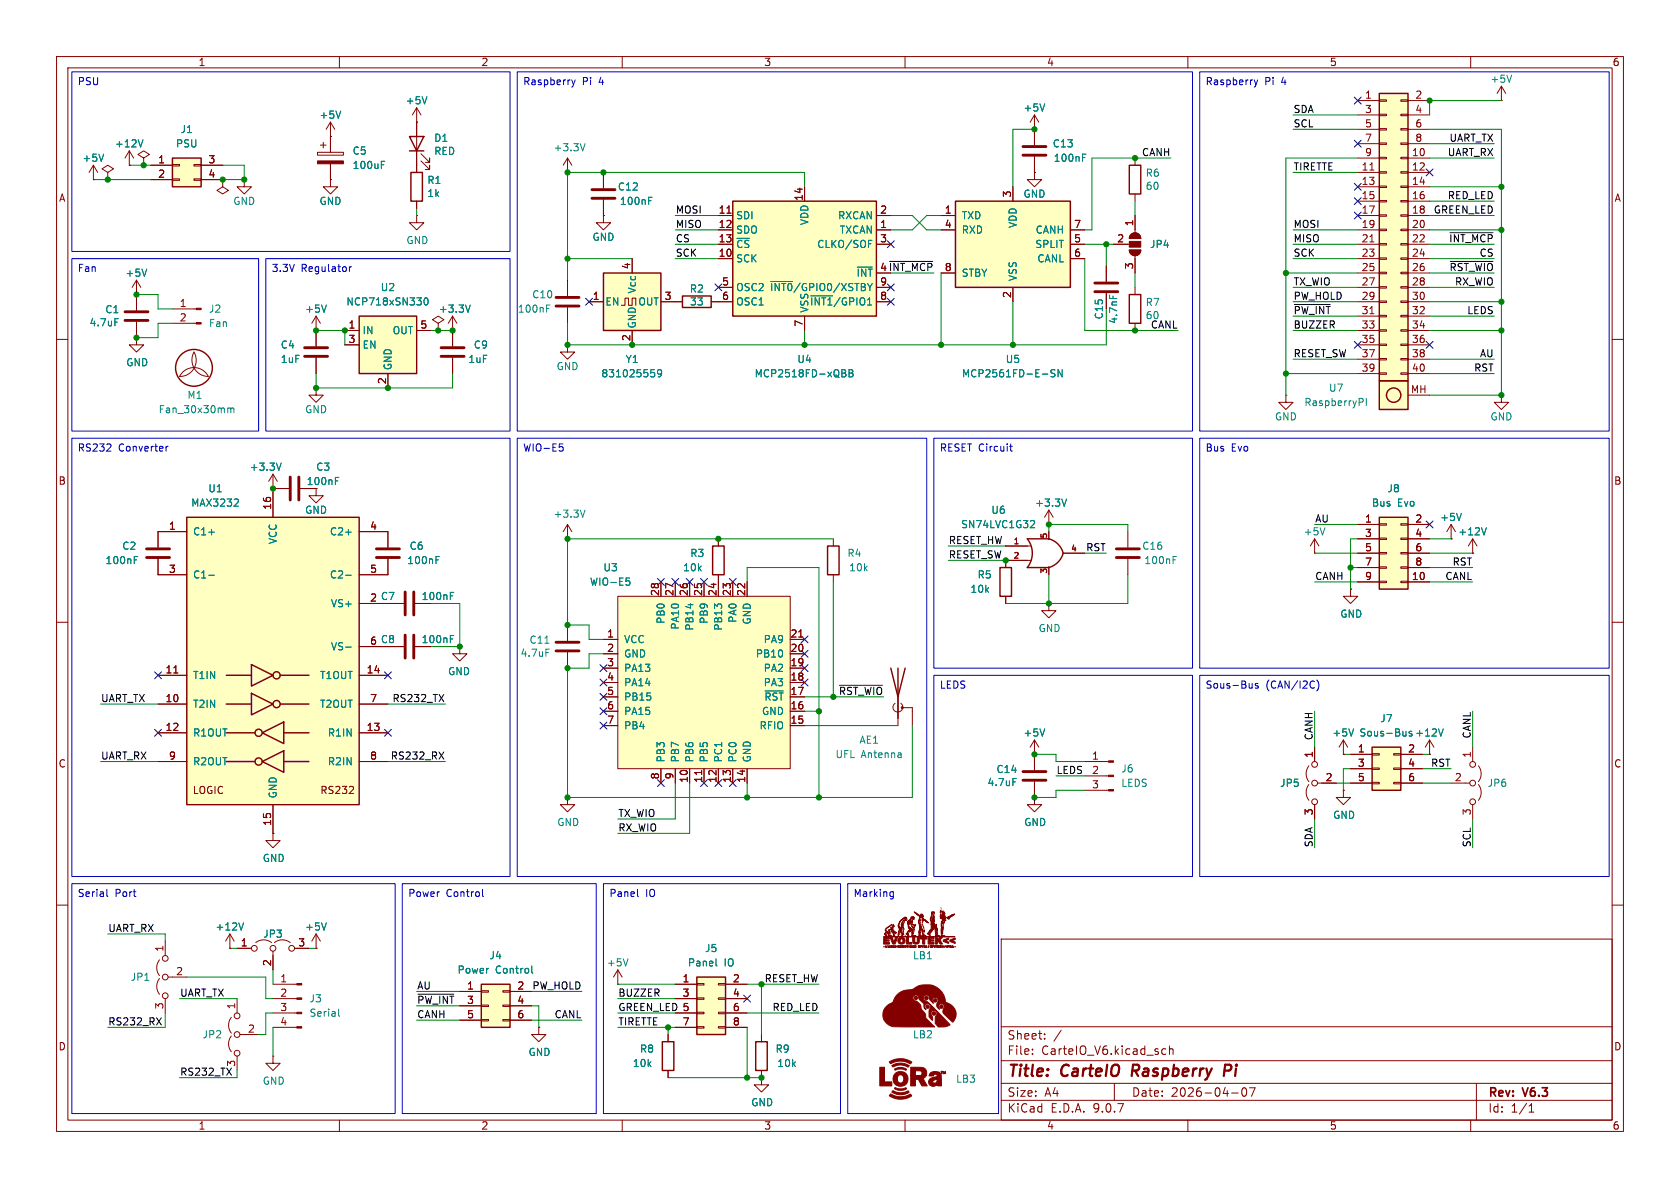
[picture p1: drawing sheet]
<svg xmlns="http://www.w3.org/2000/svg" width="297mm" height="210mm" viewBox="0 0 297 210" stroke-linecap="round" stroke-linejoin="round" font-family="sans-serif">
<defs><g id="words">
<g font-size="2.8" fill="#840000">
<text x="178" y="190.9">Title:</text>
<text x="187.7" y="190.9">CarteIO</text>
<text x="200.9" y="190.9">Raspberry</text>
<text x="218" y="190.9">Pi</text>
</g>
<g font-size="2.1" fill="#840000">
<text x="178" y="184">Sheet:</text>
<text x="178" y="186.7">File:</text>
<text x="184.1" y="186.7">CarteIO_V6.kicad_sch</text>
<text x="178" y="196.9">KiCad</text>
<text x="178" y="194.1">Size:</text>
<text x="184.7" y="194.1">A4</text>
<text x="185.7" y="196.9">E.D.A.</text>
<text x="193.3" y="196.9">9.0.7</text>
<text x="200" y="194.1">Date:</text>
<text x="207" y="194.1">2026-04-07</text>
<text x="263" y="194.3">Rev:</text>
<text x="263" y="196.9">Id:</text>
<text x="267.1" y="196.9">1/1</text>
<text x="269.4" y="194.3">V6.3</text>
</g>
<g font-size="1.8" fill="#840000">
<text x="35" y="11.9">1</text>
<text x="85" y="11.9">2</text>
<text x="135" y="11.9">3</text>
<text x="185" y="11.9">4</text>
<text x="235" y="11.9">5</text>
<text x="285" y="11.9">6</text>
<text x="241.2" y="17.5">1</text>
<text x="250.1" y="17.5">2</text>
<text x="241.2" y="20.1">3</text>
<text x="241.2" y="22.6">5</text>
<text x="250.1" y="20.1">4</text>
<text x="250.1" y="22.6">6</text>
<text x="27.9" y="29">1</text>
<text x="36.8" y="29">3</text>
<text x="241.2" y="25.1">7</text>
<text x="241.2" y="27.7">9</text>
<text x="249.5" y="27.7">10</text>
<text x="250.1" y="25.1">8</text>
<text x="10.3" y="35.9">A</text>
<text x="27.9" y="31.5">2</text>
<text x="36.8" y="31.5">4</text>
<text x="142" y="35.6" transform="rotate(-90 142 35.6)">14</text>
<text x="178.8" y="35" transform="rotate(-90 178.8 35)">3</text>
<text x="240.6" y="30.2">11</text>
<text x="240.6" y="32.8">13</text>
<text x="240.6" y="35.3">15</text>
<text x="249.5" y="30.2">12</text>
<text x="249.5" y="32.8">14</text>
<text x="249.5" y="35.3">16</text>
<text x="285.3" y="35.9">A</text>
<text x="127" y="37.8">11</text>
<text x="127" y="40.4">12</text>
<text x="155.5" y="37.8">2</text>
<text x="155.5" y="40.4">1</text>
<text x="166.9" y="37.8">1</text>
<text x="166.9" y="40.4">4</text>
<text x="189.8" y="40.4">7</text>
<text x="200.4" y="40.1" transform="rotate(-90 200.4 40.1)">1</text>
<text x="240.6" y="37.8">17</text>
<text x="240.6" y="40.4">19</text>
<text x="249.5" y="37.8">18</text>
<text x="249.5" y="40.4">20</text>
<text x="111.5" y="47.7" transform="rotate(-90 111.5 47.7)">4</text>
<text x="127" y="42.9">13</text>
<text x="127" y="45.5">10</text>
<text x="155.5" y="42.9">3</text>
<text x="189.8" y="42.9">5</text>
<text x="189.8" y="45.5">6</text>
<text x="197.4" y="42.9">2</text>
<text x="200.4" y="47.7" transform="rotate(-90 200.4 47.7)">3</text>
<text x="240.6" y="42.9">21</text>
<text x="240.6" y="45.5">23</text>
<text x="249.5" y="42.9">22</text>
<text x="249.5" y="45.5">24</text>
<text x="104.7" y="53.1">1</text>
<text x="117.4" y="53.1">3</text>
<text x="127.6" y="50.5">5</text>
<text x="127.6" y="53.1">6</text>
<text x="155.5" y="48">4 ~{INT_MCP}8</text>
<text x="155.5" y="50.5">9</text>
<text x="155.5" y="53.1">8</text>
<text x="155.5" y="48">4</text>
<text x="166.9" y="48">8</text>
<text x="178.8" y="52.8" transform="rotate(-90 178.8 52.8)">2</text>
<text x="240.6" y="48">25</text>
<text x="240.6" y="50.5">27</text>
<text x="240.6" y="53.1">29</text>
<text x="249.5" y="48">26</text>
<text x="249.5" y="50.5">28</text>
<text x="249.5" y="53.1">30</text>
<text x="31.7" y="54.4">1</text>
<text x="31.7" y="56.9">2</text>
<text x="61.5" y="58.2">1</text>
<text x="74.2" y="58.2">5</text>
<text x="142" y="57.9" transform="rotate(-90 142 57.9)">7</text>
<text x="240.6" y="55.6">31</text>
<text x="240.6" y="58.2">33</text>
<text x="249.5" y="55.6">32</text>
<text x="249.5" y="58.2">34</text>
<text x="61.5" y="60.7">3</text>
<text x="111.5" y="60.4" transform="rotate(-90 111.5 60.4)">2</text>
<text x="240.6" y="60.7">35</text>
<text x="240.6" y="63.2">37</text>
<text x="240.6" y="65.8">39</text>
<text x="249.5" y="60.7">36</text>
<text x="249.5" y="63.2">38</text>
<text x="249.5" y="65.8">40</text>
<text x="68.3" y="68" transform="rotate(-90 68.3 68)">2</text>
<text x="249.3" y="69.6">MH</text>
<text x="10.3" y="85.9">B</text>
<text x="54.1" y="86">100nF</text>
<text x="285.3" y="85.9">B</text>
<text x="29.8" y="93.7">1</text>
<text x="48" y="90.2" transform="rotate(-90 48 90.2)">16</text>
<text x="65.3" y="93.7">4</text>
<text x="241.2" y="92.5">1</text>
<text x="241.2" y="95">3</text>
<text x="250.1" y="92.5">2</text>
<text x="250.1" y="95">4</text>
<text x="29.8" y="101.3">3</text>
<text x="65.3" y="101.3">5</text>
<text x="241.2" y="97.5">5</text>
<text x="241.2" y="100.1">7</text>
<text x="250.1" y="97.5">6</text>
<text x="250.1" y="100.1">8</text>
<text x="65.3" y="106.4">2 C7</text>
<text x="116.6" y="105.5" transform="rotate(-90 116.6 105.5)">28</text>
<text x="119.1" y="105.5" transform="rotate(-90 119.1 105.5)">27</text>
<text x="121.7" y="105.5" transform="rotate(-90 121.7 105.5)">26</text>
<text x="124.2" y="105.5" transform="rotate(-90 124.2 105.5)">25</text>
<text x="126.7" y="105.5" transform="rotate(-90 126.7 105.5)">24</text>
<text x="129.3" y="105.5" transform="rotate(-90 129.3 105.5)">23</text>
<text x="131.8" y="105.5" transform="rotate(-90 131.8 105.5)">22</text>
<text x="241.2" y="102.6">9</text>
<text x="249.5" y="102.6">10</text>
<text x="107.2" y="112.8">1</text>
<text x="139.7" y="112.8">21</text>
<text x="29.2" y="119.1">11</text>
<text x="64.7" y="119.1">14</text>
<text x="65.3" y="114">6 C8</text>
<text x="107.2" y="115.3">2</text>
<text x="107.2" y="117.9">3</text>
<text x="139.7" y="115.3">20</text>
<text x="139.7" y="117.9">19</text>
<text x="29.2" y="124.2">10</text>
<text x="65.3" y="124.2">7</text>
<text x="107.2" y="120.4">4</text>
<text x="107.2" y="122.9">5</text>
<text x="107.2" y="125.5">6</text>
<text x="139.7" y="120.4">18</text>
<text x="139.7" y="122.9">17</text>
<text x="139.7" y="125.5">16</text>
<text x="29.2" y="129.3">12</text>
<text x="64.7" y="129.3">13</text>
<text x="107.2" y="128">7</text>
<text x="139.7" y="128">15</text>
<text x="10.3" y="135.9">C</text>
<text x="29.8" y="134.4">9</text>
<text x="65.3" y="134.4">8</text>
<text x="116.6" y="137.9" transform="rotate(-90 116.6 137.9)">8</text>
<text x="119.1" y="137.9" transform="rotate(-90 119.1 137.9)">9</text>
<text x="193" y="134.4">1</text>
<text x="193" y="136.9">2</text>
<text x="232.2" y="134.1" transform="rotate(-90 232.2 134.1)">1</text>
<text x="240" y="133.1">1</text>
<text x="240" y="135.6">3</text>
<text x="248.8" y="133.1">2</text>
<text x="248.8" y="135.6">4</text>
<text x="260.1" y="134.1" transform="rotate(-90 260.1 134.1)">1</text>
<text x="285.3" y="135.9">C</text>
<text x="34" y="140.6">LOGIC</text>
<text x="56.5" y="140.6">RS232</text>
<text x="121.7" y="138.5" transform="rotate(-90 121.7 138.5)">10</text>
<text x="124.2" y="138.5" transform="rotate(-90 124.2 138.5)">11</text>
<text x="126.7" y="138.5" transform="rotate(-90 126.7 138.5)">12</text>
<text x="129.3" y="138.5" transform="rotate(-90 129.3 138.5)">13</text>
<text x="131.8" y="138.5" transform="rotate(-90 131.8 138.5)">14</text>
<text x="193" y="139.4">3</text>
<text x="234.2" y="138.2">2</text>
<text x="240" y="138.2">5</text>
<text x="248.8" y="138.2">6</text>
<text x="257.1" y="138.2">2</text>
<text x="48" y="146.1" transform="rotate(-90 48 146.1)">15</text>
<text x="232.2" y="144.2" transform="rotate(-90 232.2 144.2)">3</text>
<text x="260.1" y="144.2" transform="rotate(-90 260.1 144.2)">3</text>
<text x="42.5" y="167.4">1</text>
<text x="52.6" y="167.4">3</text>
<text x="29" y="168.3" transform="rotate(-90 29 168.3)">1</text>
<text x="31" y="172.5">2</text>
<text x="48" y="170.9" transform="rotate(-90 48 170.9)">2</text>
<text x="49.5" y="173.7">1</text>
<text x="120.6" y="173.7">1</text>
<text x="129.5" y="173.7">2</text>
<text x="29" y="178.5" transform="rotate(-90 29 178.5)">3</text>
<text x="41.7" y="178.5" transform="rotate(-90 41.7 178.5)">1</text>
<text x="49.5" y="176.3">2</text>
<text x="49.5" y="178.8">3</text>
<text x="82.5" y="175">1</text>
<text x="82.5" y="177.5">3</text>
<text x="91.4" y="175">2</text>
<text x="91.4" y="177.5">4</text>
<text x="120.6" y="176.3">3</text>
<text x="120.6" y="178.8">5</text>
<text x="129.5" y="176.3">4</text>
<text x="129.5" y="178.8">6</text>
<text x="10.3" y="185.9">D</text>
<text x="43.7" y="182.6">2</text>
<text x="49.5" y="181.4">4</text>
<text x="82.5" y="180.1">5</text>
<text x="91.4" y="180.1">6</text>
<text x="120.6" y="181.4">7</text>
<text x="129.5" y="181.4">8</text>
<text x="285.3" y="185.9">D</text>
<text x="41.7" y="188.7" transform="rotate(-90 41.7 188.7)">3</text>
<text x="35" y="199.9">1</text>
<text x="85" y="199.9">2</text>
<text x="135" y="199.9">3</text>
<text x="185" y="199.9">4</text>
<text x="235" y="199.9">5</text>
<text x="285" y="199.9">6</text>
</g>
<g font-size="1.8" fill="#0000c2">
<text x="13.7" y="15.4">PSU</text>
<text x="92.4" y="15.4">Raspberry</text>
<text x="102.9" y="15.4">Pi</text>
<text x="106" y="15.4">4</text>
<text x="213" y="15.4">Raspberry</text>
<text x="223.6" y="15.4">Pi</text>
<text x="226.6" y="15.4">4</text>
<text x="13.7" y="48.4">Fan</text>
<text x="47.9" y="48.4">3.3V</text>
<text x="53.2" y="48.4">Regulator</text>
<text x="13.7" y="80.1">RS232</text>
<text x="20.9" y="80.1">Converter</text>
<text x="92.4" y="80.1">WIO-E5</text>
<text x="166.1" y="80.1">RESET Circuit</text>
<text x="213" y="80.1">Bus</text>
<text x="217.7" y="80.1">Evo</text>
<text x="166.1" y="122.1">LEDS</text>
<text x="213" y="122.1">Sous-Bus</text>
<text x="223.8" y="122.1">(CAN/I2C)</text>
<text x="13.7" y="158.9">Serial</text>
<text x="20.3" y="158.9">Port</text>
<text x="72.1" y="158.9">Power</text>
<text x="78.9" y="158.9">Control</text>
<text x="107.6" y="158.9">Panel</text>
<text x="114.1" y="158.9">IO</text>
<text x="150.8" y="158.9">Marking</text>
</g>
<g font-size="1.8" fill="#008484">
<text x="263.4" y="14.8">+5V</text>
<text x="31.8" y="23.7">J1</text>
<text x="56.4" y="21.2">+5V</text>
<text x="71.6" y="18.6">+5V</text>
<text x="180.8" y="19.9">+5V</text>
<text x="14.5" y="28.8">+5V</text>
<text x="20.2" y="26.3">+12V</text>
<text x="31" y="26.3">PSU</text>
<text x="62.2" y="27.5">C5</text>
<text x="76.7" y="25.3">D1</text>
<text x="76.7" y="27.6">RED</text>
<text x="97.8" y="26.9">+3.3V</text>
<text x="186" y="26.3">C13</text>
<text x="186.2" y="28.8">100nF</text>
<text x="62.2" y="30.1">100uF</text>
<text x="75.4" y="32.7">R1</text>
<text x="75.4" y="35">1k</text>
<text x="109.1" y="33.9">C12</text>
<text x="180.8" y="35.2">GND</text>
<text x="202.4" y="31.4">R6</text>
<text x="202.4" y="33.8">60</text>
<text x="41.1" y="36.4">GND</text>
<text x="56.4" y="36.4">GND</text>
<text x="109.5" y="36.4">100nF</text>
<text x="130" y="39">SDI</text>
<text x="130" y="41.5">SDO</text>
<text x="143.1" y="39.9" transform="rotate(-90 143.1 39.9)">VDD</text>
<text x="148.1" y="39">RXCAN</text>
<text x="148.4" y="41.5">TXCAN</text>
<text x="169.9" y="39">TXD</text>
<text x="169.9" y="41.5">RXD</text>
<text x="179.9" y="40.4" transform="rotate(-90 179.9 40.4)">VDD</text>
<text x="183" y="41.5">CANH</text>
<text x="71.8" y="43.4">GND</text>
<text x="104.6" y="42.8">GND</text>
<text x="130" y="44">~{CS}</text>
<text x="130" y="46.6">SCK</text>
<text x="144.4" y="44">CLKO/SOF</text>
<text x="182.9" y="44">SPLIT</text>
<text x="183.3" y="46.6">CANL</text>
<text x="203.2" y="44">JP4</text>
<text x="22.1" y="49.1">+5V</text>
<text x="67.2" y="51.7">U2</text>
<text x="94" y="52.9">C10</text>
<text x="112.6" y="52" transform="rotate(-90 112.6 52)">Vcc</text>
<text x="121.8" y="51.9">R2</text>
<text x="130" y="51.7">OSC2 ~{INT0}/GPIO0/XSTBY</text>
<text x="151.3" y="49.1">~{INT}</text>
<text x="169.9" y="49.1">STBY</text>
<text x="179.9" y="49.8" transform="rotate(-90 179.9 49.8)">VSS</text>
<text x="15.7" y="57.9">4.7uF</text>
<text x="18.5" y="55.6">C1</text>
<text x="36.8" y="55.5">J2</text>
<text x="36.8" y="58">Fan</text>
<text x="53.8" y="55.5">+5V</text>
<text x="61.1" y="54.2">NCP718xSN330</text>
<text x="64" y="59.3">IN</text>
<text x="69.3" y="59.3">OUT</text>
<text x="77.5" y="55.5">+3.3V</text>
<text x="91.4" y="55.5">100nF</text>
<text x="106.9" y="54.2">EN</text>
<text x="112.6" y="58.2" transform="rotate(-90 112.6 58.2)">GND</text>
<text x="112.8" y="54.2">OUT</text>
<text x="121.9" y="54.2">33</text>
<text x="130" y="54.2">OSC1</text>
<text x="143.1" y="54.2">~{INT1}/GPIO1</text>
<text x="143.1" y="55.4" transform="rotate(-90 143.1 55.4)">VSS</text>
<text x="195.2" y="56.6" transform="rotate(-90 195.2 56.6)">C15</text>
<text x="197.7" y="57.3" transform="rotate(-90 197.7 57.3)">4.7nF</text>
<text x="202.4" y="54.3">R7</text>
<text x="22.2" y="64.9">GND</text>
<text x="49.5" y="61.8">C4</text>
<text x="49.5" y="64.4">1uF</text>
<text x="64" y="61.8">EN</text>
<text x="69.4" y="65.5" transform="rotate(-90 69.4 65.5)">GND</text>
<text x="82.7" y="64.4">1uF</text>
<text x="83.7" y="61.8">C9</text>
<text x="98.3" y="65.6">GND</text>
<text x="110.5" y="64.4">Y1</text>
<text x="140.9" y="64.4">U4</text>
<text x="177.7" y="64.4">U5</text>
<text x="33" y="70.7">M1</text>
<text x="106.2" y="66.9">831025559</text>
<text x="133.3" y="66.9">MCP2518FD-xQBB</text>
<text x="170" y="66.9">MCP2561FD-E-SN</text>
<text x="230.5" y="72">RaspberryPI</text>
<text x="234.8" y="69.4">U7</text>
<text x="27.9" y="73.3">Fan_30x30mm</text>
<text x="53.8" y="73.3">GND</text>
<text x="225.3" y="74.5">GND</text>
<text x="263.4" y="74.5">GND</text>
<text x="44" y="83.4">+3.3V</text>
<text x="55.8" y="83.4">C3</text>
<text x="33.7" y="89.8">MAX3232</text>
<text x="36.7" y="87.2">U1</text>
<text x="182.9" y="89.8">+3.3V</text>
<text x="242.4" y="89.8">Bus</text>
<text x="245.2" y="87.2">J8</text>
<text x="247.1" y="89.8">Evo</text>
<text x="34" y="94.8">C1+</text>
<text x="53.8" y="91">GND</text>
<text x="58.2" y="94.8">C2+</text>
<text x="97.8" y="91.7">+3.3V</text>
<text x="169.8" y="93.6">SN74LVC1G32</text>
<text x="175.2" y="91">U6</text>
<text x="230.4" y="94.8">+5V</text>
<text x="254.5" y="92.3">+5V</text>
<text x="257.7" y="94.8">+12V</text>
<text x="18.6" y="99.9">100nF</text>
<text x="21.5" y="97.4">C2</text>
<text x="49.1" y="96.3" transform="rotate(-90 49.1 96.3)">VCC</text>
<text x="71.9" y="99.9">100nF</text>
<text x="72.3" y="97.4">C6</text>
<text x="106.6" y="101.2">U3</text>
<text x="120.7" y="101.2">10k</text>
<text x="121.9" y="98.7">R3</text>
<text x="149.7" y="98.7">R4</text>
<text x="150" y="101.2">10k</text>
<text x="201.8" y="97.4">C16</text>
<text x="202.2" y="99.9">100nF</text>
<text x="34" y="102.5">C1-</text>
<text x="58.2" y="102.5">C2-</text>
<text x="58.4" y="107.5">VS+</text>
<text x="74.4" y="106.3">100nF</text>
<text x="104.2" y="103.7">WIO-E5</text>
<text x="171.5" y="105">10k</text>
<text x="172.7" y="102.5">R5</text>
<text x="74.4" y="113.9">100nF</text>
<text x="93.5" y="114">C11</text>
<text x="110.2" y="113.9">VCC</text>
<text x="117.7" y="110.4" transform="rotate(-90 117.7 110.4)">PB0</text>
<text x="120.2" y="111.4" transform="rotate(-90 120.2 111.4)">PA10</text>
<text x="122.8" y="111.6" transform="rotate(-90 122.8 111.6)">PB14</text>
<text x="125.3" y="110.4" transform="rotate(-90 125.3 110.4)">PB9</text>
<text x="127.9" y="111.6" transform="rotate(-90 127.9 111.6)">PB13~{}</text>
<text x="130.4" y="110.2" transform="rotate(-90 130.4 110.2)">PA0</text>
<text x="132.9" y="110.5" transform="rotate(-90 132.9 110.5)">GND</text>
<text x="134.9" y="113.9">PA9</text>
<text x="183.5" y="111.9">GND</text>
<text x="236.9" y="109.4">GND</text>
<text x="58.4" y="115.2">VS-</text>
<text x="79.1" y="119.6">GND</text>
<text x="91.9" y="116.3">4.7uF</text>
<text x="110.2" y="116.4">GND</text>
<text x="110.2" y="119">PA13</text>
<text x="133.5" y="116.4">PB10</text>
<text x="134.9" y="119">PA2</text>
<text x="34" y="120.2">T1IN</text>
<text x="34" y="125.3">T2IN</text>
<text x="56.5" y="120.2">T1OUT</text>
<text x="56.5" y="125.3">T2OUT</text>
<text x="110.2" y="121.5">PA14</text>
<text x="110.2" y="124.1">PB15</text>
<text x="134.9" y="121.5">PA3</text>
<text x="135" y="124.1">~{RST}</text>
<text x="34" y="130.4">R1OUT</text>
<text x="57.9" y="130.4">R1IN</text>
<text x="110.2" y="126.6">PA15</text>
<text x="110.2" y="129.1">PB4</text>
<text x="134.2" y="129.1">RFIO</text>
<text x="134.6" y="126.6">GND</text>
<text x="151.8" y="131.7">AE1</text>
<text x="180.8" y="130.4">+5V</text>
<text x="235.5" y="130.4">+5V</text>
<text x="240.2" y="130.4">Sous-Bus</text>
<text x="243.9" y="127.9">J7</text>
<text x="250.1" y="130.4">+12V</text>
<text x="34" y="135.5">R2OUT</text>
<text x="57.9" y="135.5">R2IN</text>
<text x="117.7" y="134.9" transform="rotate(-90 117.7 134.9)">PB3</text>
<text x="120.2" y="134.9" transform="rotate(-90 120.2 134.9)">PB7</text>
<text x="122.8" y="134.9" transform="rotate(-90 122.8 134.9)">PB6</text>
<text x="125.3" y="134.9" transform="rotate(-90 125.3 134.9)">PB5</text>
<text x="127.9" y="134.9" transform="rotate(-90 127.9 134.9)">PC1</text>
<text x="130.4" y="134.9" transform="rotate(-90 130.4 134.9)">PC0</text>
<text x="132.9" y="134.9" transform="rotate(-90 132.9 134.9)">GND</text>
<text x="147.6" y="134.2">UFL</text>
<text x="152.2" y="134.2">Antenna</text>
<text x="176.1" y="136.9">C14</text>
<text x="198.1" y="136.8">J6</text>
<text x="49.1" y="141.2" transform="rotate(-90 49.1 141.2)">GND</text>
<text x="174.5" y="139.2">4.7uF</text>
<text x="198.1" y="139.3">LEDS</text>
<text x="226.2" y="139.3">JP5</text>
<text x="262.9" y="139.3">JP6</text>
<text x="98.4" y="146.2">GND</text>
<text x="181" y="146.2">GND</text>
<text x="235.6" y="145">GND</text>
<text x="46.4" y="152.6">GND</text>
<text x="38" y="164.7">+12V</text>
<text x="46.4" y="166">JP3</text>
<text x="53.8" y="164.7">+5V</text>
<text x="23" y="173.6">JP1</text>
<text x="80.8" y="172.3">Power</text>
<text x="86.4" y="169.8">J4</text>
<text x="87.6" y="172.3">Control</text>
<text x="107.2" y="171">+5V</text>
<text x="121.5" y="171">Panel</text>
<text x="124.5" y="168.5">J5</text>
<text x="128" y="171">IO</text>
<text x="161.3" y="169.8">LB1</text>
<text x="54.6" y="177.4">J3</text>
<text x="54.6" y="179.9">Serial</text>
<text x="35.7" y="183.7">JP2</text>
<text x="161.3" y="183.7">LB2</text>
<text x="46.4" y="191.9">GND</text>
<text x="93.3" y="186.9">GND</text>
<text x="111.8" y="188.8">10k</text>
<text x="113" y="186.3">R8</text>
<text x="137" y="186.3">R9</text>
<text x="137.3" y="188.8">10k</text>
<text x="168.9" y="191.6">LB3</text>
<text x="132.7" y="195.8">GND</text>
</g>
<g font-size="1.8">
<text x="228.6" y="22.6">SCL</text>
<text x="228.6" y="20.1">SDA</text>
<text x="201.8" y="27.7">CANH</text>
<text x="255.9" y="27.7">UART_RX</text>
<text x="256.2" y="25.1">UART_TX</text>
<text x="228.6" y="30.2">TIRETTE</text>
<text x="255.9" y="35.3">RED_LED</text>
<text x="119.4" y="40.4">MISO</text>
<text x="119.4" y="37.8">MOSI</text>
<text x="228.6" y="40.4">MOSI</text>
<text x="253.4" y="37.8">GREEN_LED</text>
<text x="119.4" y="42.9">CS</text>
<text x="119.4" y="45.5">SCK</text>
<text x="228.6" y="42.9">MISO</text>
<text x="228.6" y="45.5">SCK</text>
<text x="256.1" y="42.9">~{INT_MCP}</text>
<text x="256.2" y="48">~{RST_WIO}</text>
<text x="261.5" y="45.5">CS</text>
<text x="228.6" y="53.1">PW_HOLD</text>
<text x="228.6" y="50.5">TX_WIO</text>
<text x="257.1" y="50.5">RX_WIO</text>
<text x="202.4" y="56.6">60</text>
<text x="203.4" y="58.2">CANL</text>
<text x="228.6" y="58.2">BUZZER</text>
<text x="228.6" y="55.6">~{PW_INT}</text>
<text x="259.3" y="55.6">LEDS</text>
<text x="228.6" y="63.2">RESET_SW</text>
<text x="260.5" y="65.8">RST</text>
<text x="261.5" y="63.2">AU</text>
<text x="232.4" y="92.4">AU</text>
<text x="167.6" y="98.8">RESET_SW</text>
<text x="167.6" y="96.3">RESET_HW</text>
<text x="191.9" y="97.5">RST</text>
<text x="256.7" y="100.1">RST</text>
<text x="232.4" y="102.6">CANH</text>
<text x="255.4" y="102.6">CANL</text>
<text x="17.8" y="124.2">UART_TX</text>
<text x="69.3" y="124.2">RS232_TX</text>
<text x="148.2" y="122.9">~{RST_WIO}</text>
<text x="232.1" y="131" transform="rotate(-90 232.1 131)">CANH</text>
<text x="260.1" y="130.7" transform="rotate(-90 260.1 130.7)">CANL</text>
<text x="17.8" y="134.4">UART_RX</text>
<text x="69" y="134.4">RS232_RX</text>
<text x="186.7" y="136.9">LEDS</text>
<text x="252.9" y="135.6">RST</text>
<text x="109.2" y="144.5">TX_WIO</text>
<text x="109.2" y="147.1">RX_WIO</text>
<text x="232.1" y="149.9" transform="rotate(-90 232.1 149.9)">SDA</text>
<text x="260.1" y="149.9" transform="rotate(-90 260.1 149.9)">SCL</text>
<text x="19" y="164.8">UART_RX</text>
<text x="135.1" y="173.7">RESET_HW</text>
<text x="31.7" y="176.3">UART_TX</text>
<text x="73.7" y="177.5">~{PW_INT}3</text>
<text x="73.7" y="175">AU</text>
<text x="94" y="175">PW_HOLD</text>
<text x="109.2" y="178.8">GREEN_LED 5</text>
<text x="109.2" y="176.3">BUZZER</text>
<text x="136.5" y="178.8">RED_LED</text>
<text x="19" y="181.3">RS232_RX</text>
<text x="73.7" y="180.1">CANH</text>
<text x="97.9" y="180.1">CANL</text>
<text x="109.2" y="181.3">TIRETTE</text>
<text x="31.7" y="190.2">RS232_TX</text>
</g>
<g font-size="1.4" fill="#840000">
<text x="185.2" y="95.3" transform="rotate(-90 185.2 95.3)">5</text>
<text x="179.1" y="96.3">1</text>
<text x="179.1" y="98.8">2</text>
<text x="185.2" y="101.5" transform="rotate(-90 185.2 101.5)">3</text>
<text x="189.3" y="97.5">4</text>
</g>
</g></defs>
<path d="M0 0h297v210h-297z" fill="#fff" stroke="#fff" stroke-width=".18"/>
<g fill="none" stroke="#840000" stroke-width=".18">
<path d="M10 10h277v190h-277zM12 12h273v186h-273zM60 10v2M110 10v2M160 10v2M210 10v2M260 10v2M19 30.5l1.1-.7-1.1-.6-1 .6 1 .7v1.3M19 31.8h.1M39.4 31.8v1.2l1 .7-1 .6-1-.6 1-.7M39.4 31.8h.1M24.1 59.7v1.3h1.3l-1.3 1.2-1.2-1.2h1.2"/>
<path d="M24.1 59.7h.1M10 60h2M34.3 62.2a2.87 2.87 0 0 1-2.6 4.3 2.84 2.84 0 0 1 2.6-1.5 2.84 2.84 0 0 1 2.5 1.5 2.92 2.92 0 0 1-2.5-4.3zM285 60h2M147.3 95.3v1.2M177.8 96.5h4.4M182.2 99.1h-4.4v1.2M185.4 92.7h.1M185.4 90.2l-.7 1.2M185.4 90.2l.8 1.2M185.4 90.2v2.5M185.4 94v1.4"/>
<path d="M188 97.8h3.8M10 110h2M147.3 101.6v1.3M177.8 105.4v1.3M185.4 100.2v1.4M285 110h2M252.7 133.4h.1M252.7 130.8l-.7 1.3M252.7 130.8l.8 1.3M252.7 130.8v2.6M10 160h2M40.6 167.6h.1"/>
<path d="M40.6 165.1l-.7 1.3M40.6 165.1l.8 1.3M40.6 165.1v2.5M177 166h108v32h-108zM285 160h2M48.3 186.7v1.3h1.2l-1.2 1.2-1.3-1.2h1.3M48.3 186.7h.1M60 198v2M110 198v2M160 198v2M177 194.5h108M177 191.5h108"/>
<path d="M177 187.5h108M177 181.5h108M182.5 186.3v.1M182.5 185.5v.1M184.7 183.6v.1M184.7 182.8v.1M187.6 182.1l-1.3 2M197 191.5v3M205.5 186.3h.6M205.5 185.5h.6M206.7 185.5l.3-.1 .3 .1 .1 .9M206.7 184.9v1.5"/>
<path d="M210 198v2M217.7 193.2h1.2M219.7 192.4l.2-.1a.81 .81 0 0 1 .6 .6 .81 .81 0 0 1-.3 .8l-.2 .1a.81 .81 0 0 1-.3-1.4zM220.9 192.3h1l-.7 1.5M260 198v2M261 191.5v6.5M270.3 196.6h.9M270.3 195.5l.4-.4v1.5"/>
</g>
<path d="M200.3 188.2l-.2 2M217.4 188.2h-.8l-.3 2M217.4 189.2l-.9 .1" fill="none" stroke="#840000" stroke-width=".4"/>
<path d="M40.3 72.1v.9M40.3 72.2l.3-.1 .2 .2M40.8 72.3l.2-.2 .3 .1 .1 .8M40.8 72.3v.7M182.4 92l.4 .1 .1 .3-.8 .9h.8M188.6 88.2l-.5 1.3M255.1 128.8l-.4 1.3M43.1 163.1l-.5 1.3" fill="none" stroke="#008484" stroke-width=".18"/>
<g fill="none" stroke="#840000" stroke-width=".25">
<path d="M146.3 96.5h2v5.1h-2zM181.6 95.3h3.8a3.6 3.6 0 0 1 2.6 2.5 3.7 3.7 0 0 1-2.6 2.5h-3.8a4.1 4.1 0 0 0 0-5zM176.8 100.3h2v5.1h-2z"/>
<circle cx="34.3" cy="65" r="3.3"/>
</g>
<path d="M181.6 95.3h3.8M181.6 100.3h3.8" fill="none" stroke="#ffffc2" stroke-width=".18"/>
<path d="M106.7 48.3h10.1v10.1h-10.1z" fill="#ffffc2"/>
<path d="M72.4 24.1h2.5l-1.2 2.6zM72.4 26.7h2.5M72.6 30.5h2.1v5.1h-2.1zM106.7 48.3h10.1v10.1h-10.1zM117.1 184.2h2v5h-2z" fill="none" stroke="#840000" stroke-width=".25"/>
<g fill="none" stroke="#840000" stroke-width=".18">
<path d="M73.7 38.1v1.3h1.2l-1.2 1.2-1.3-1.2h1.3M73.7 38.1h.1M73.7 21.6v8.9M73.7 35.6v1.2M74.4 28.4l1.5 1.6v-.8v.8h-.7M74.4 27.2l1.5 1.5v-.8v.8h-.7M106.7 30.5v2.8M106.7 35.3v2.8M24.1 52.1v2.8M24.1 56.9v2.8M30.5 54.6h4.2M30.5 57.2h4.2"/>
<path d="M80 58.4h.1M80 55.9l-.8 1.3M80 55.9l.8 1.3M80 55.9v2.5M104.1 53.3h2.6M109.9 54h.6v-1.3h.6v1.3h.7v-1.3h.6v1.3M111.8 45.7v2.6M111.8 58.4v2.6M116.8 53.3h2.6M48.3 86.4h.1M48.3 83.8l-.8 1.3M48.3 83.8l.7 1.3"/>
<path d="M48.3 83.8v2.6M182.9 141v1.2h1.2l-1.2 1.3-1.3-1.3h1.3M182.9 141h.1M118.1 182.9v1.3M118.1 189.2v1.3M134.6 190.5v1.3h1.3l-1.3 1.2-1.3-1.2h1.3M134.6 190.5h.1"/>
</g>
<path d="M114.7 35.5h.4M114.7 34.9h.6M20.3 56.3h.6M83.1 53.9l-.4 1.3M115.1 65.3h.6M115.5 65.8l.3 .3v.3l-.3 .2M117 65.9l-.3 .2h-.3l-.2-.2 .2-.5 .3-.1 .2 .2a.84 .84 0 0 1-.3 1.1h-.2M49.7 81.9l-.4 1.2" fill="none" stroke="#008484" stroke-width=".18"/>
<g fill="#840000" stroke="#840000" stroke-width=".18">
<path d="M34.7 54.5h.9v.2h-.9z"/>
<path d="M34.7 57h.9v.3h-.9z"/>
</g>
<path d="M104.6 33.5h4.1M104.6 35.1h4.1M22.1 55.1h4.1M22.1 56.6h4.1" fill="none" stroke="#840000" stroke-width=".51"/>
<path d="M168.9 35.6h20.3v15.2h-20.3z" fill="#ffffc2"/>
<path d="M168.9 35.6h20.3v15.2h-20.3z" fill="none" stroke="#840000" stroke-width=".25"/>
<path d="M166.4 38.1h2.5M179.1 33v2.6M100.3 49.5v2.8M100.3 54.4v2.8M166.4 40.6h2.5M166.4 48.3h2.5M179.1 50.8v2.5M189.2 40.6h2.6M189.2 43.2h2.6M189.2 45.7h2.6" fill="none" stroke="#840000" stroke-width=".18"/>
<path d="M96.6 54.5h.5M96.6 53.9h.6M186.5 65.4l-.5-.1-.2 .2v.3l.6 .3 .1 .3-.2 .2h-.5M187.8 65.3v1.3l-.7-1.3v1.3" fill="none" stroke="#008484" stroke-width=".18"/>
<path d="M98.3 52.6h4.1M98.3 54.1h4.1" fill="none" stroke="#840000" stroke-width=".51"/>
<path d="M129.5 35.6h25.4v20.3h-25.4z" fill="#ffffc2"/>
<path d="M129.5 35.6h25.4v20.3h-25.4z" fill="none" stroke="#840000" stroke-width=".25"/>
<g fill="none" stroke="#840000" stroke-width=".18">
<path d="M127 38.1h2.5M128.5 37.7h.7M142.2 33v2.6M154.9 38.1h2.6M182.9 22.9h.1M182.9 30.5v1.3h1.2l-1.2 1.2-1.3-1.2h1.3M182.9 30.5h.1M182.9 20.3l-.8 1.3M182.9 20.3l.7 1.3M182.9 20.3v5.4M182.9 27.7v2.8M127 40.6h2.5"/>
<path d="M127 43.2h2.5M127 45.7h2.5M127 50.8h2.5M127 53.3h2.5M142.2 55.9v2.5M154.9 40.6h2.6M154.9 43.2h2.6M154.9 50.8h2.6M154.9 53.3h2.6M260.3 97.8h.1M260.3 95.3l-.7 1.2M260.3 95.3l.8 1.2"/>
<path d="M260.3 95.3v2.5M238.8 104.1v1.3h1.2l-1.2 1.3-1.3-1.3h1.3M238.8 104.1h.1"/>
</g>
<path d="M184.7 18.4l-.4 1.2M191.4 27.9h.4M191.4 27.2h.6M136.3 49.8h3.8M143.3 52.3h3.9M151.6 47.2h2.6M153.5 43.1h.5M153.5 42.5h.7M149.3 65.3l.2 .3-.2 .4 .2 .1 .1 .3-.3 .2h-.5M150.1 65.3h.4l.3 .3-.3 .4 .3 .1v.3l-.2 .2h-.5zM150.1 66h.4M262.8 93.3l-.5 1.3" fill="none" stroke="#008484" stroke-width=".18"/>
<path d="M180.8 27.4h4.1M180.8 25.9h4.1" fill="none" stroke="#840000" stroke-width=".51"/>
<path d="M243.8 91.4h5.1v12.7h-5.1z" fill="#ffffc2"/>
<path d="M199.6 29.2h2.1v5.1h-2.1zM199.6 52.1h2.1v5.1h-2.1zM243.8 91.4h5.1v12.7h-5.1z" fill="none" stroke="#840000" stroke-width=".25"/>
<g fill="none" stroke="#840000" stroke-width=".18">
<path d="M100.3 30.5h.1M100.3 27.9l-.7 1.3M100.3 27.9l.8 1.3M100.3 27.9v2.6M200.7 27.9v1.3M200.7 34.3v1.3M200.7 38.1v3M55.9 58.4h.1M55.9 55.9l-.8 1.3M55.9 55.9l.7 1.3M55.9 55.9v2.5M80 58.4v2.8"/>
<path d="M195.6 47v2.8M195.6 51.8v2.8M196.8 43.2h2.8M199.6 44.2h2.1a1.02 1.02 0 0 1-1 1 1.02 1.02 0 0 1-1.1-1zM199.9 41.5a1.02 1.02 0 0 1 1.1-.3 1.02 1.02 0 0 1 .7 1h-2.1zM200.7 45.2v3.1M200.7 50.8v1.3M200.7 57.2v1.2M55.9 68.6v1.3h1.2l-1.2 1.2-1.3-1.2h1.3M55.9 68.6h.1M80 63.2v2.8M100.3 61v1.2h1.3l-1.3 1.3-1.2-1.3h1.2"/>
<path d="M100.3 61h.1M232.4 97.8h.1M232.4 95.3l-.8 1.2M232.4 95.3l.8 1.2M232.4 95.3v2.5M240 92.7h3.8M240 95.3h3.8M240 97.8h3.8M243.8 92.6h1.3v.2h-1.3zM243.8 95.1h1.3v.3h-1.3zM243.8 97.7h1.3v.2h-1.3zM247.6 92.6h1.3v.2h-1.3z"/>
<path d="M247.6 95.1h1.3v.3h-1.3zM247.6 97.7h1.3v.2h-1.3zM248.9 92.7h3.8M248.9 95.3h3.8M248.9 97.8h3.8M256.5 95.3h.1M256.5 92.7l-.7 1.3M256.5 92.7l.8 1.3M256.5 92.7v2.6M185.4 106.7v1.3h1.3l-1.3 1.2-1.3-1.2h1.3M185.4 106.7h.1M240 100.3h3.8"/>
<path d="M240 102.9h3.8M243.8 100.2h1.3v.3h-1.3zM243.8 102.7h1.3v.3h-1.3zM247.6 100.2h1.3v.3h-1.3zM247.6 102.7h1.3v.3h-1.3zM248.9 100.3h3.8M248.9 102.9h3.8M182.9 133.4h.1M182.9 130.8v5.3M182.9 138.2v2.8M182.9 130.8l-.8 1.3M182.9 130.8l.7 1.3"/>
<path d="M48.3 174h4.2M48.3 176.5h4.2M48.3 179.1h4.2M48.3 181.6h4.2"/>
</g>
<path d="M103.4 25.4l-.4 1.3M57.7 53.9l-.4 1.3M196.2 52.2v.6M234.2 93.3l-.4 1.3M258.4 90.7l-.5 1.3M179.1 137.6h.6M184.7 128.8l-.4 1.3M59.9 178.4v1.1l.1 .1" fill="none" stroke="#008484" stroke-width=".18"/>
<path d="M193.5 51.6h4.1M193.5 50h4.1M78 61.5h4M78 63h4M180.8 136.4h4.1M180.8 137.9h4.1" fill="none" stroke="#840000" stroke-width=".51"/>
<g fill="#840000" stroke="#840000" stroke-width=".18">
<path d="M199.9 41.5a1.02 1.02 0 0 1 1.1-.3 1.02 1.02 0 0 1 .7 1h-2.1z"/>
<path d="M199.6 42.7h2.1v1h-2.1z"/>
<path d="M199.6 44.2h2.1a1.02 1.02 0 0 1-1 1 1.02 1.02 0 0 1-1.1-1z"/>
<path d="M52.5 173.9h.8v.2h-.8z"/>
<path d="M52.5 176.4h.8v.3h-.8z"/>
<path d="M52.5 178.9h.8v.3h-.8z"/>
<path d="M52.5 181.5h.8v.2h-.8z"/>
</g>
<path d="M63.5 55.9h10.2v10.1h-10.2z" fill="#ffffc2"/>
<path d="M63.5 55.9h10.2v10.1h-10.2z" fill="none" stroke="#840000" stroke-width=".25"/>
<path d="M55.9 58.4v2.8M61 58.4h2.5M73.7 58.4h2.5M77.5 57.2l1-.7-1-.6-1 .6 1 .7v1.2M77.5 58.4h.1M55.9 63.2v2.8M61 61h2.5M68.6 66v2.6" fill="none" stroke="#840000" stroke-width=".18"/>
<path d="M75.1 52.7l.2-.1a.68 .68 0 0 1 .4 .7 .68 .68 0 0 1-.4 .6 .84 .84 0 0 1-.2-1.2z" fill="none" stroke="#008484" stroke-width=".18"/>
<path d="M53.8 61.5h4.1M53.8 63h4.1" fill="none" stroke="#840000" stroke-width=".51"/>
<path d="M30.5 27.9h5.1v5.1h-5.1z" fill="#ffffc2"/>
<path d="M30.5 27.9h5.1v5.1h-5.1z" fill="none" stroke="#840000" stroke-width=".25"/>
<g fill="none" stroke="#840000" stroke-width=".18">
<path d="M16.5 31.8h.1M16.5 29.2l-.8 1.3M16.5 29.2l.8 1.3M16.5 29.2v2.6M22.9 29.2h.1M22.9 26.7l-.8 1.2M22.9 26.7l.7 1.2M22.9 26.7v2.5M26.7 29.2h3.8M26.7 31.8h3.8M30.5 29.1h1.2v.2h-1.2zM30.5 31.6h1.2v.3h-1.2z"/>
<path d="M34.3 29.1h1.3v.2h-1.3zM34.3 31.6h1.3v.3h-1.3zM35.6 29.2h3.8M35.6 31.8h3.8M58.4 31.8v1.2h1.3l-1.3 1.3-1.3-1.3h1.3M58.4 31.8h.1M55.9 86.4v1.2h1.2l-1.2 1.3-1.3-1.3h1.3"/>
</g>
<path d="M18.3 27.2l-.4 1.3M25.3 24.7l-.4 1.3" fill="none" stroke="#008484" stroke-width=".18"/>
<g fill="#840000" stroke="#840000" stroke-width=".18">
<path d="M156.2 167.3l.2 .1z"/>
<path d="M156.6 165.2l.1 .1z"/>
<path d="M156.6 167.2l.2 .3h-.2z"/>
<path d="M156.9 167.2v.1z"/>
<path d="M157.1 167.2h.2l.1 .3h-.4l.1-.2h.1h-.1z"/>
<path d="M157.1 164.4l.1 .1 .2-.3-.2 .3z"/>
<path d="M156.2 165.7h1v.2h-.6v.3h.6v.2h-.6v.2h.6v.3h-1z"/>
<path d="M156.7 164.1l1-.7-.3 .3a1.04 1.04 0 0 0-.8 .8l.5 .3v.6h.5h-.6v-.6l-.2 .2 .2-.2h-.2a.27 .27 0 0 0-.3 .2 .27 .27 0 0 0 .1 .3l.2 .1a.27 .27 0 0 1-.3-.1 .27 .27 0 0 1-.1-.3 .31 .31 0 0 0 .3-.3 .31 .31 0 0 0-.2-.3z"/>
<path d="M157.2 164.5l.1 .6z"/>
<path d="M157.4 167.2h.3h-.2l.2 .2-.3 .1 .2-.1z"/>
<path d="M157.7 163.8l.1 .2z"/>
<path d="M157.8 164.1v.2z"/>
<path d="M157.8 164l.1 .4z"/>
<path d="M157.8 167.2h.2h-.1l.1 .1a.15 .15 0 0 1-.1 .2 .15 .15 0 0 1-.1-.1h.2z"/>
<path d="M157.8 163.7l.2 .1h-.2h.2z"/>
<path d="M157.5 163.9l.1 .2a.9 .9 0 0 0 .4 1l.1 .3-.2-.1v-.3a.85 .85 0 0 1-.4-1z"/>
<path d="M157.4 165.7h.3l.3 .8 .3-.8h.4l-.5 1.2a.45 .45 0 0 1-.4-.1 .45 .45 0 0 1-.2-.4z"/>
<path d="M157.9 163.4l.1 .4z"/>
<path d="M158 164.9l.1 .1z"/>
<path d="M158.2 165.3l-.1 .1z"/>
<path d="M158.1 165.1l.1 .1z"/>
<path d="M158.2 167.2a.18 .18 0 0 1 .3 0 .18 .18 0 0 1-.1 .3 .18 .18 0 0 1-.3-.1h.3l-.1-.2-.2 .2z"/>
<path d="M157.8 164.5l.6 .5-.4-.3v.1z"/>
<path d="M158.4 164.8v.2z"/>
<path d="M158.7 167.2h.3v.3l-.2-.1-.1 .1v-.3l.2 .1z"/>
<path d="M159.2 164.8l-.1 .1z"/>
<path d="M159.3 164.6l-.1 .1z"/>
<path d="M159.2 167.2v-.1a.18 .18 0 0 1 .2 .2 .18 .18 0 0 1-.1 .2 .18 .18 0 0 1-.2-.2l.2 .1-.1-.2-.1 .1z"/>
<path d="M159.7 162.6v.2a1.36 1.36 0 0 0-.2 1.2l-.2-.7z"/>
<path d="M158.9 165.8a.65 .65 0 0 1 1.1 .2 .65 .65 0 0 1-.5 .9 .65 .65 0 0 1-.7-.7h.3v.2a.27 .27 0 0 0 .4 .2 .27 .27 0 0 0 .1-.4 .26 .26 0 0 0-.2-.2 .26 .26 0 0 0-.3 .2h-.3z"/>
<path d="M159.2 162.7a.74 .74 0 0 1 .8-.3v-.1l-.3 .1 .1-.1a.28 .28 0 0 1 .3-.2 .28 .28 0 0 1 .2 .3l-.1-.1-.1 .1 .2 .3-.3-.1a.33 .33 0 0 0-.3-.2 .33 .33 0 0 0-.3 .2l-.1 .1a.87 .87 0 0 0 0 1.3 .52 .52 0 0 1 .2 .8l.1 .6h-.2v-.9a.37 .37 0 0 0-.4 .1 .37 .37 0 0 0-.1 .4v.3h-.1l.2-1h.4h-.4l-.2-.4 .6 .4-.6-.4v-.2z"/>
<path d="M159.5 167.2h.3v.2l-.3 .1v-.1h.2h-.2v-.2h.2z"/>
<path d="M159.8 163.1l-.2 .8a.56 .56 0 0 1 .2-.8z"/>
<path d="M159.6 164v.1z"/>
<path d="M159.7 164.8v.2z"/>
<path d="M159.6 163.9l.1 .2z"/>
<path d="M159.7 164.6v.1z"/>
<path d="M159.7 165.1l.1 .1z"/>
<path d="M159.9 167.2a.18 .18 0 0 1 .3 0 .18 .18 0 0 1-.1 .3 .18 .18 0 0 1-.2-.2l.2 .1v-.1z"/>
<path d="M160.3 167.2h.3l-.1 .3z"/>
<path d="M160.6 165v.2z"/>
<path d="M160.7 167.2v.3z"/>
<path d="M160.8 164.7l.1-.1z"/>
<path d="M160.9 167.2a.21 .21 0 0 1 .2 0 .21 .21 0 0 1 .1 .3l-.3-.1-.1-.1 .3 .1-.1-.2-.2 .1z"/>
<path d="M161.1 163.6l.1 .1z"/>
<path d="M160.2 165.7h.4v.9h.6v.3h-1z"/>
<path d="M161.2 162.6v.1z"/>
<path d="M161.2 162.8v.2l.1-.1-.1 .3z"/>
<path d="M161.2 163.7l.1 .2z"/>
<path d="M161.3 162.7v.1z"/>
<path d="M161.5 165v.1z"/>
<path d="M161.3 163.9l.2 .2z"/>
<path d="M161.3 167.2l.1 .2 .1-.2a.19 .19 0 0 1 .1 .2 .19 .19 0 0 1-.3 .1 .19 .19 0 0 1 0-.3z"/>
<path d="M161.6 163.7v.3z"/>
<path d="M161.5 164.1l.1 .3z"/>
<path d="M161.1 162.1a.32 .32 0 0 1 .5 .2l-.1-.1 .1 .3h-.2l-.1-.3v.3h-.3a.71 .71 0 0 0 0 .7 .71 .71 0 0 0 .7 .3l.2 .1-.7-.1-.3-.2-.1-.5-.1 .6a.56 .56 0 0 0 .5 .8 .46 .46 0 0 1 .1 .7 .4 .4 0 0 0 .1 .4 .4 .4 0 0 0 .5 .1h-.7l.1-1-.1-.2-.1 .2a.78 .78 0 0 0-.7 .8l.3 .2a.33 .33 0 0 1-.4-.2 .33 .33 0 0 1 .2-.5l.1-.1a.24 .24 0 0 0 .2-.2 .24 .24 0 0 0-.1-.3l.4 .1-.4-.1-.1-.1 .3 .1a.57 .57 0 0 1-.4-.7l-.1-.3 .2 .3 .1-.6-.3 .2z"/>
<path d="M161.8 163.4l.1 .1z"/>
<path d="M161.7 167.2h.3h-.2l.1 .1-.1 .1 .2 .1h-.3z"/>
<path d="M161.4 165.7h.3l.1 .9a.21 .21 0 0 0 .2 0 .21 .21 0 0 0 .1-.2l.1-.7h.3v.5a.6 .6 0 0 1-.6 .7 .6 .6 0 0 1-.5-.8z"/>
<path d="M162.3 167.2h.3h-.1l.1 .1-.1 .1 .1 .1h-.3z"/>
<path d="M162.7 163v.2z"/>
<path d="M162.7 165v.1z"/>
<path d="M162.8 162.7l-.1 .1z"/>
<path d="M162.7 164.8v.1z"/>
<path d="M162.8 164.6v.1z"/>
<path d="M162.8 162.5v.1z"/>
<path d="M162.7 167.2l.3 .1-.2 .2-.1-.2h.2z"/>
<path d="M162.7 163.4l.1 .2z"/>
<path d="M163.1 162.9v.3z"/>
<path d="M163 163.4l.1 .1z"/>
<path d="M163.1 167.2v.3z"/>
<path d="M163.4 164.3v.5z"/>
<path d="M163.3 167.2h.3l-.2 .3z"/>
<path d="M162.7 165.7h1.2v.3h-.4v.9h-.4v-.9h-.4z"/>
<path d="M156.2 165.6h12.6z"/>
<path d="M161.6 161.2l1 .7h.3h-.3a.3 .3 0 0 1 .3-.3 .3 .3 0 0 1 .3 .3l-.2-.2v.3l.2 .1a.3 .3 0 0 0 .2 .5h.1l.6 .5-.6-.4-.4 .1v-.4v.4l.3-.2-.4-.2-.1-.3a1.12 1.12 0 0 0-.1 1.6v.2l.3 .5 .1 1 .5 .1h-.6l-.1-1.2a.7 .7 0 0 0-.4 1l-.1 .1h.4h-.5v-.7l.2-.5h.3h-.3v-.3h.2l.1 .2-.1-.2h-.2v-.1a1.72 1.72 0 0 1 0-1.7v-.1h.6h-.6z"/>
<path d="M163.7 167.2l.2 .3h-.3v-.2h.2h-.2z"/>
<path d="M164.2 167.2l-.1 .3z"/>
<path d="M164.4 167.2h.3h-.2l.2 .1-.2 .1 .2 .1h-.3z"/>
<path d="M164.8 167.2h.3l-.3 .3v-.2l.2-.1-.2 .1z"/>
<path d="M164.7 161.2h.4l.1 .2-.3-.1-.1 .4-.1-.1z"/>
<path d="M164.9 162v.1z"/>
<path d="M164.8 162.3l.3 .6-.2 .1-.1-.5z"/>
<path d="M164.1 165.7h1v.2h-.6v.3h.6v.2h-.6v.2h.6v.3h-1z"/>
<path d="M165 161.8l.1-.1 .1 .4-.1 .9z"/>
<path d="M165.2 167.2v.3z"/>
<path d="M165.1 163.2l.3 .5z"/>
<path d="M165.3 167.2h.3l-.1 .3z"/>
<path d="M165.6 163.4l.1 1-.3-.7 .1 .2z"/>
<path d="M165.7 164.4v.2z"/>
<path d="M165.7 164.7v.2z"/>
<path d="M165.7 165v.2z"/>
<path d="M165.7 167.2h.3h-.2l.2 .1-.2 .1 .2 .1h-.3z"/>
<path d="M164.7 161.7l-.1 .9 .2 .8h.1v-.3h.2l-.1 .1a2.08 2.08 0 0 1 .6 2l.5 .3h-.7l-.1-1.3-.3-.2-.1 .4-.5 .6h-.1l.2 .3a.41 .41 0 0 1-.5-.3l.4-.5h.4l.2-.3v-.3l-.3 .6h-.3l.2-.3v-1.3a.89 .89 0 0 1 .1-1.1z"/>
<path d="M166.3 160.9l-.1 .5z"/>
<path d="M166.1 167.2h.2l-.1 .1 .2 .1a.18 .18 0 0 1-.3 .1 .18 .18 0 0 1 0-.3z"/>
<path d="M165.3 165.7h.4v.4h.1a.55 .55 0 0 1 .8-.4l-.1 .2a.32 .32 0 0 0-.3 .3 .32 .32 0 0 0 .2 .3l.2 .4h-.1a.47 .47 0 0 1-.6-.5l-.2 .2v.3h-.4z"/>
<path d="M166.4 161.1l.1 .1z"/>
<path d="M166.5 167.2l.1 .1 .2-.1v.3l-.2-.1-.1 .1z"/>
<path d="M166.3 161.5v.3a.29 .29 0 0 0 .2 .5v-.5l.2 .4a.53 .53 0 0 1-.2 .8l.2 .2h-.1l-.1 .7 .3-.1-.2 1.3 .1-1.1a.16 .16 0 0 0-.3 .1 .16 .16 0 0 0 .2 .2l-.1 .1-.1 1 .6 .1h-.6v-2.6a.4 .4 0 0 0 .2-.6 .2 .2 0 0 1-.3 .1 .2 .2 0 0 1-.1-.3z"/>
<path d="M166.7 161.8l.1 .1z"/>
<path d="M166.8 163.6v.1z"/>
<path d="M166.6 161.1l.5 .4-.1 .1-.4-.3 .2 .3-.1 .2v.2l.3 .6 .2 .1h-.3v.5h-.1v-.1h.1v-.4l-.3-.8 .1-.3z"/>
<path d="M166.8 163.4v.1z"/>
<path d="M166.7 161.3l.1 .3z"/>
<path d="M166.8 161.6l.1 .4h-.1z"/>
<path d="M166.8 161.1l.1 .1z"/>
<path d="M166.9 161.3l.1 .1z"/>
<path d="M167.1 167.2l-.1 .3z"/>
<path d="M167 161.8l.1 .7z"/>
<path d="M167.4 167.2v.3z"/>
<path d="M167.3 162.2l1.1-.5-.9 .5z"/>
<path d="M167.5 167.2h.3l-.2 .3-.1-.2h.2z"/>
<path d="M166.8 166.2l.9-.4v.3l-.5 .2 .5 .2v.3l-.9-.4z"/>
<path d="M167.6 162.3l1.1-.7v.1l-.5 .3a.42 .42 0 0 0-.5 .4l.2-.1-.2 .2z"/>
<path d="M167.9 167.2h.2h-.1l.2 .2-.3 .1 .2-.1z"/>
<path d="M168.3 167.2l.3 .3h-.4l.1-.2h.1h-.1z"/>
<path d="M167.9 166.2l.9-.4a.3 .3 0 0 1 0 .4 .3 .3 0 0 1-.4 0l-.1 .1 .6 .2v.3l-1-.4z"/>
<path d="M168.8 167.3l.1 .1z"/>
<path d="M155.5 188.7h.9v2.6h1.3v.7h-2.2z"/>
<path d="M158.2 192.3a3 3 0 0 0 2 0 .58 .58 0 0 1-.7 .4h-.7a.48 .48 0 0 1-.6-.4z"/>
<path d="M157.4 193.4h.1a3.4 3.4 0 0 0 3.5 0l.2 .3a3.4 3.4 0 0 1-4 0z"/>
<path d="M158.2 189.9a1.33 1.33 0 0 1 2.1 0 1.33 1.33 0 0 1-.6 2 1.33 1.33 0 0 1-1.8-1.1v-.1h.7a.6 .6 0 0 0 .6 .8 .6 .6 0 0 0 .6-.8 .59 .59 0 0 0-.6-.7 .59 .59 0 0 0-.6 .7h-.7z"/>
<path d="M157.9 192.8a2.55 2.55 0 0 0 2.6 0l.2 .3a2.78 2.78 0 0 1-3 0z"/>
<path d="M158.1 189a1.75 1.75 0 0 1 2.2 .1 .39 .39 0 0 1-.6-.1h-.9l-.5 .2z"/>
<path d="M157.7 188.4a2.84 2.84 0 0 1 3.1 0l-.3 .2a2.5 2.5 0 0 0-2.7 0z"/>
<path d="M157.2 187.7a3.7 3.7 0 0 1 4 .1l-.2 .3a3.6 3.6 0 0 0-3.6-.1z"/>
<path d="M161 188.7h1a1.66 1.66 0 0 1 1.7 .5 1.24 1.24 0 0 1-.5 1.5l.7 1.3h-.9l-.6-1.2h-.6v1.2h-.8v-1.9h1.3a.48 .48 0 0 0 .7-.4 .48 .48 0 0 0-.7-.4h-.5v.8h-.8z"/>
<path d="M164.5 189.7a1.2 1.2 0 0 1 1.9 .4v1.9h-.6v-.3l-.3 .2a.84 .84 0 0 1-.9 0 .84 .84 0 0 1-.4-.7h.7a.39 .39 0 0 0 .5 .2 .39 .39 0 0 0 .1-.6l-.6 .4h-.7a1.3 1.3 0 0 1 1.5-.9 .35 .35 0 0 0-.3-.4 .35 .35 0 0 0-.4 .3h-.7z"/>
<path d="M166.3 189.4h.4l-.1 .1-.1 .3z"/>
<path d="M166.8 189.4l.2 .3 .1-.3 .1 .4-.1-.3-.1 .3-.2-.2v.2z"/>
<path d="M158.6 175.8a4.1 4.1 0 0 1 2.7-.9 3.9 3.9 0 0 1 4.8 0 4.6 4.6 0 0 1 1.2 2.3 2.04 2.04 0 0 1 1.6 1.4 2.04 2.04 0 0 1-.5 2.1l-.6-.6a2.08 2.08 0 0 1-1.1-1.3v-.3a.55 .55 0 0 0 0-1 .55 .55 0 0 0-.8 .6l.2 .3a.86 .86 0 0 1-.3-1.4 .53 .53 0 0 0-.5-.7 .53 .53 0 0 0-.4 .8l.1 .3-.6-.7a.6 .6 0 0 0-.3-.7 .6 .6 0 0 0-.7 .1 .62 .62 0 0 0 .5 .9l4.1 4.1-.9 .4h-1.2a1.24 1.24 0 0 1-.6-1.5l.1-.3a.57 .57 0 0 0 .1-.9 .57 .57 0 0 0-.8 0 .57 .57 0 0 0 .1 .9l.1 .7a1.46 1.46 0 0 1-.6-1.8v-.1a.57 .57 0 0 0 .2-.9 .57 .57 0 0 0-.9 0 .57 .57 0 0 0 .1 .9 .77 .77 0 0 1-.4-1.1l-.9-.9a.56 .56 0 0 0-.5-.6 .56 .56 0 0 0-.6 .6 .56 .56 0 0 0 .7 .5 1.51 1.51 0 0 1 .9 1.4l.1 .2a1.36 1.36 0 0 1 .7 1.4l1.5 1.5h-5.7a3.5 3.5 0 0 1-2.7-.6 2.19 2.19 0 0 1 1-3.7z"/>
<circle cx="161.9" cy="176.4" r=".32"/>
<circle cx="163.8" cy="176.4" r=".31"/>
<circle cx="164" cy="178" r=".31"/>
<circle cx="165.1" cy="179.2" r=".32"/>
<circle cx="165.3" cy="176.9" r=".3"/>
<circle cx="166.4" cy="178" r=".31"/>
</g>
<path d="M123.2 172.7h5.1v10.2h-5.1z" fill="#ffffc2"/>
<path d="M120.6 52.3h5.1v2.1h-5.1zM126 96.5h2v5.1h-2zM123.2 172.7h5.1v10.2h-5.1z" fill="none" stroke="#840000" stroke-width=".25"/>
<g fill="none" stroke="#840000" stroke-width=".18">
<path d="M73.7 19.1l-.8 1.2M73.7 19.1l.7 1.2M73.7 19.1v2.5M73.7 21.6h.1M119.4 53.3h1.2M125.7 53.3h1.3M127 95.3v1.2M127 101.6v1.3M109.2 174h.1M109.2 171.5l-.7 1.2M109.2 171.5l.8 1.2M109.2 171.5v2.5"/>
<path d="M119.4 174h3.8M119.4 176.5h3.8M119.4 179.1h3.8M123.2 173.9h1.3v.2h-1.3zM123.2 176.4h1.3v.3h-1.3zM123.2 178.9h1.3v.3h-1.3zM127 173.9h1.3v.2h-1.3zM127 176.4h1.3v.3h-1.3zM127 178.9h1.3v.3h-1.3zM128.3 174h3.8M128.3 176.5h3.8M128.3 179.1h3.8"/>
<path d="M119.4 181.6h3.8M123.2 181.5h1.3v.2h-1.3zM127 181.5h1.3v.2h-1.3zM128.3 181.6h3.8"/>
</g>
<path d="M75.5 17.1l-.4 1.3M111 169.5l-.4 1.3M126.6 169.5v1.1l.2 .2" fill="none" stroke="#008484" stroke-width=".18"/>
<path d="M109.2 105.4h30.5v30.5h-30.5z" fill="#ffffc2"/>
<g fill="none" stroke="#840000" stroke-width=".18">
<path d="M56.1 26.9h4.6v.5h-4.6zM56.6 25.7h1.1M57.1 25.1v1.1M58.4 24.1h.1M58.4 21.6v5.3M58.4 29v2.8M58.4 21.6l-.7 1.3M58.4 21.6l.8 1.3M106.7 38.1v1.3h1.2l-1.2 1.2-1.3-1.2h1.3M106.7 38.1h.1M68.6 94v2.8M68.6 98.8v2.8"/>
<path d="M100.3 95.3h.1M100.3 92.7v2.6M100.3 92.7l-.7 1.3M100.3 92.7l.8 1.3M68.6 114.3h2.8M68.6 106.7h2.8M73.4 114.3h2.8M73.4 106.7h2.8M81.3 114.3v1.3h-1.3l1.3 1.2 1.2-1.2h-1.2M81.3 114.3h.1M100.3 110.5v2.8M100.3 115.3v2.8"/>
<path d="M106.7 113h2.5M106.7 115.6h2.5M106.7 118.1h2.5M109.2 105.4h30.5v30.5h-30.5zM116.8 102.9v2.5M119.4 102.9v2.5M121.9 102.9v2.5M124.5 102.9v2.5M127 102.9v2.5M129.5 102.9v2.5M132.1 102.9v2.5M139.7 113h2.5"/>
<path d="M139.7 115.6h2.5M139.7 118.1h2.5M141.2 112.6h.7M106.7 120.7h2.5M106.7 123.2h2.5M106.7 125.7h2.5M106.7 128.3h2.5M116.8 135.9v2.5M119.4 135.9v2.5M121.9 135.9v2.5M124 136.2v.7M124.5 135.9v2.5"/>
<path d="M127 135.9v2.5M129.5 135.9v2.5M132.1 135.9v2.5M139.7 120.7h2.5M139.7 123.2h2.5M139.7 125.7h2.5M139.7 128.3h2.5M158.2 124.3a.85 .85 0 0 0-.1 1.3 .85 .85 0 0 0 1.3 0 .85 .85 0 0 0-.1-1.3M158.7 123.2v5.1M159.5 125.1h1.8v3.2M191.8 134.6h4.2M191.8 137.2h4.2"/>
<path d="M191.8 139.7h4.2M48.3 147.3v1.3h1.2l-1.2 1.3-1.3-1.3h1.3M48.3 147.3h.1M134.6 182.9v1.3M134.6 189.2v1.3"/>
</g>
<g fill="none" stroke="#008484" stroke-width=".18">
<path d="M60.2 19.6l-.4 1.3M67.4 29.1h.4M67.4 28.5h.6M77.1 99h.4M77.1 98.4h.6M103.4 90.2l-.4 1.2M79.6 112.9h.4M79.6 112.3h.6M79.6 105.3h.4M79.6 104.7h.6M96.3 113.7h.8M96.5 114.8h.6"/>
<path d="M110.7 102.2h.6M110.8 102.7h.3l.3 .2-.1 .4-.5 .1M135.3 122.1h3.2"/>
</g>
<g fill="#840000" stroke="#840000" stroke-width=".18">
<path d="M56.1 28.4h4.6v.6h-4.6z"/>
<path d="M196 134.5h.8v.2h-.8z"/>
<path d="M196 137h.8v.3h-.8z"/>
<path d="M196 139.6h.8v.2h-.8z"/>
<circle cx="159.5" cy="125.1" r=".18"/>
</g>
<path d="M66.5 98.6h4.1M66.5 97h4.1M71.6 104.6v4.1M71.6 112.3v4M73.2 104.6v4.1M73.2 112.3v4M98.3 113.5h4.1M98.3 115.1h4.1" fill="none" stroke="#840000" stroke-width=".51"/>
<path d="M157.5 118.1l1.2 5.1 1.3-5.1M158.7 118.1v8.9M133.6 184.2h2v5h-2z" fill="none" stroke="#840000" stroke-width=".25"/>
<path d="M33 91.4h30.5v50.8h-30.5z" fill="#ffffc2"/>
<g fill="none" stroke="#840000" stroke-width=".25">
<path d="M33 91.4h30.5v50.8h-30.5zM40 119.4h4.4M44.4 117.5l3.9 1.9-3.9 1.9zM49.5 119.4h5.1M40 124.5h4.4M40 129.5h5.1M40 134.6h5.1M44.4 122.6l3.9 1.9-3.9 1.9zM46.4 129.5l3.8-1.9v3.8zM46.4 134.6l3.8-1.9v3.8zM49.5 124.5h5.1M50.2 129.5h4.4"/>
<path d="M50.2 134.6h4.4"/>
<circle cx="48.9" cy="119.4" r=".63"/>
<circle cx="45.7" cy="134.6" r=".63"/>
<circle cx="45.7" cy="129.5" r=".63"/>
<circle cx="48.9" cy="124.5" r=".63"/>
</g>
<g fill="none" stroke="#840000" stroke-width=".18">
<path d="M25.4 27.9l1-.6-1-.6-1 .6 1 .6v1.3M25.4 29.2h.1M265.4 69.9v1.2h1.3l-1.3 1.3-1.2-1.3h1.2M265.4 69.9h.1M27.9 98.8v2.8h5.1M33 94h-5.1v2.8M51.1 86.4h-2.8v5M53.1 86.4h2.8M63.5 94h5.1M199.4 94v2.8M199.4 98.8v2.8M27.9 119.4h5.1"/>
<path d="M30.7 119h.7M63.5 101.6h5.1M63.5 119.4h5.1M63.5 106.7h5.1M63.5 114.3h5.1M27.9 124.5h5.1M27.9 129.5h5.1M27.9 134.6h5.1M62.4 139.1v.5M63.5 124.5h5.1M63.5 129.5h5.1M63.5 134.6h5.1"/>
<path d="M48.3 142.2v5.1M61.7 140.3h.8"/>
</g>
<path d="M23.7 99h.5M23.7 98.4h.6M36.9 94.1h1M41.9 88.2l.3 .3-.1 .3-.7 .7h.8M59.3 85h.4M59.3 84.4h.6M61.1 94.1h1M207.4 99h.4M207.4 98.4h.6M36.9 101.7h1M61.1 101.7h1M61.1 114.4h1" fill="none" stroke="#008484" stroke-width=".18"/>
<path d="M25.9 97h4.1M25.9 98.6h4.1M51.3 84.3v4.1M52.8 84.3v4.1M197.4 97h4M197.4 98.6h4" fill="none" stroke="#840000" stroke-width=".51"/>
<g fill="#ffffc2">
<path d="M243.8 67.3h5.1v5.1h-5.1z"/>
<path d="M243.8 16.5h5.1v50.8h-5.1z"/>
</g>
<g fill="none" stroke="#840000" stroke-width=".25">
<path d="M243.8 16.5h5.1v50.8h-5.1zM243.8 67.3h5.1v5.1h-5.1z"/>
<circle cx="246.4" cy="69.8" r="1.27"/>
</g>
<g fill="none" stroke="#840000" stroke-width=".18">
<path d="M240 17.8h3.8M243.8 17.7h1.3v.2h-1.3zM247.6 17.7h1.3v.2h-1.3zM248.9 17.8h3.8M265.4 17.8h.1M265.4 15.2l-.7 1.3M265.4 15.2l.8 1.3M265.4 15.2v2.6M240 20.3h3.8M240 22.9h3.8M240 25.4h3.8M240 27.9h3.8"/>
<path d="M240 30.5h3.8M240 33h3.8M240 35.6h3.8M240 38.1h3.8M242.2 30.1h.7M243.8 20.2h1.3v.2h-1.3zM243.8 22.7h1.3v.3h-1.3zM243.8 25.3h1.3v.2h-1.3zM243.8 27.8h1.3v.3h-1.3zM243.8 30.4h1.3v.2h-1.3zM243.8 32.9h1.3v.2h-1.3zM243.8 35.4h1.3v.3h-1.3z"/>
<path d="M243.8 38h1.3v.2h-1.3zM247.6 20.2h1.3v.2h-1.3zM247.6 22.7h1.3v.3h-1.3zM247.6 25.3h1.3v.2h-1.3zM247.6 27.8h1.3v.3h-1.3zM247.6 30.4h1.3v.2h-1.3zM247.6 32.9h1.3v.2h-1.3zM247.6 35.4h1.3v.3h-1.3zM247.6 38h1.3v.2h-1.3zM248.9 20.3h3.8M248.9 22.9h3.8M248.9 25.4h3.8"/>
<path d="M248.9 27.9h3.8M248.9 30.5h3.8M248.9 33h3.8M248.9 35.6h3.8M248.9 38.1h3.8M240 40.6h3.8M240 43.2h3.8M240 45.7h3.8M240 48.3h3.8M240 50.8h3.8M240 53.3h3.8M240 55.9h3.8"/>
<path d="M240 58.4h3.8M242.2 42.8h.7M242.2 55.5h.7M243.8 40.5h1.3v.3h-1.3zM243.8 43.1h1.3v.2h-1.3zM243.8 45.6h1.3v.2h-1.3zM243.8 48.1h1.3v.3h-1.3zM243.8 50.7h1.3v.2h-1.3zM243.8 53.2h1.3v.3h-1.3zM243.8 55.8h1.3v.2h-1.3zM243.8 58.3h1.3v.2h-1.3zM247.6 40.5h1.3v.3h-1.3z"/>
<path d="M247.6 43.1h1.3v.2h-1.3zM247.6 45.6h1.3v.2h-1.3zM247.6 48.1h1.3v.3h-1.3zM247.6 50.7h1.3v.2h-1.3zM247.6 53.2h1.3v.3h-1.3zM247.6 55.8h1.3v.2h-1.3zM247.6 58.3h1.3v.2h-1.3zM248.9 40.6h3.8M248.9 43.2h3.8M248.9 45.7h3.8M248.9 48.3h3.8M248.9 50.8h3.8"/>
<path d="M248.9 53.3h3.8M248.9 55.9h3.8M248.9 58.4h3.8M227.3 69.9v1.2h1.3l-1.3 1.3-1.2-1.3h1.2M227.3 69.9h.1M240 61h3.8M240 63.5h3.8M240 66h3.8M243.8 60.8h1.3v.3h-1.3zM243.8 63.4h1.3v.2h-1.3zM243.8 65.9h1.3v.3h-1.3zM247.6 60.8h1.3v.3h-1.3z"/>
<path d="M247.6 63.4h1.3v.2h-1.3zM247.6 65.9h1.3v.3h-1.3zM248.9 61h3.8M248.9 63.5h3.8M248.9 66h3.8M248.9 69.9h3.8M237.5 139.7v1.3h1.3l-1.3 1.2-1.3-1.2h1.3M237.5 139.7h.1M237.5 133.4h.1M237.5 130.8l-.8 1.3M237.5 130.8l.8 1.3M237.5 130.8v2.6"/>
<path d="M256.5 138.4h3.3M260.3 132.1v2.5M261.4 135.4a2.26 2.26 0 0 1 0 2.8M261.4 138.7a2.26 2.26 0 0 1 0 2.8M260.3 142.2v2.6"/>
<circle cx="260.3" cy="135.1" r=".51"/>
<circle cx="260.3" cy="138.4" r=".51"/>
<circle cx="260.3" cy="141.7" r=".51"/>
</g>
<path d="M267.2 13.3l-.4 1.2M240.8 70.4l.2 .3-.1 .3-.1 .1M241.5 70.4v1.3M239.3 128.8l-.4 1.3" fill="none" stroke="#008484" stroke-width=".18"/>
<path d="M242.6 132.1h5v7.6h-5z" fill="#ffffc2"/>
<path d="M242.6 132.1h5v7.6h-5z" fill="none" stroke="#840000" stroke-width=".25"/>
<g fill="none" stroke="#840000" stroke-width=".18">
<path d="M231.4 135.4a2.26 2.26 0 0 0 0 2.8M231.4 138.7a2.26 2.26 0 0 0 0 2.8M232.4 132.1v2.5M232.9 138.4h3.3M238.8 133.4h3.8M238.8 135.9h3.8M238.8 138.4h3.8M242.6 133.2h1.2v.3h-1.2zM242.6 135.8h1.2v.2h-1.2zM242.6 138.3h1.2v.3h-1.2zM246.4 133.2h1.2v.3h-1.2zM246.4 135.8h1.2v.2h-1.2z"/>
<path d="M246.4 138.3h1.2v.3h-1.2zM247.6 133.4h3.9M247.6 135.9h3.9M247.6 138.4h3.9M100.3 141v1.2h1.3l-1.3 1.3-1.2-1.3h1.2M100.3 141h.1M232.4 142.2v2.6M28.2 169.7a2.26 2.26 0 0 0 0 2.8M28.2 173a2.26 2.26 0 0 0 0 2.8M29.2 166.4v2.5M29.2 176.5v2.6M29.7 172.7h3.3"/>
<path d="M40.9 179.8a2.26 2.26 0 0 0 0 2.8M41.9 167.6h2.5M41.9 176.5v2.6M45.2 166.6a2.26 2.26 0 0 1 2.8 0M48.3 168.1v3.4M48.5 166.6a2.26 2.26 0 0 1 2.8 0M52.1 167.6h2.5M55.9 167.6h.1M55.9 165.1l-.8 1.3M55.9 165.1l.7 1.3M55.9 165.1v2.5M40.9 183.1a2.26 2.26 0 0 0 0 2.8"/>
<path d="M41.9 186.7v2.5M42.4 182.9h3.3M95.2 181.6v1.3h1.3l-1.3 1.3-1.2-1.3h1.2M95.2 181.6h.1"/>
<circle cx="232.4" cy="138.4" r=".51"/>
<circle cx="232.4" cy="135.1" r=".51"/>
<circle cx="232.4" cy="141.7" r=".51"/>
<circle cx="29.2" cy="176" r=".51"/>
<circle cx="29.2" cy="172.7" r=".51"/>
<circle cx="29.2" cy="169.4" r=".51"/>
<circle cx="41.9" cy="179.6" r=".51"/>
<circle cx="45" cy="167.6" r=".51"/>
<circle cx="48.3" cy="167.6" r=".51"/>
<circle cx="51.6" cy="167.6" r=".51"/>
<circle cx="41.9" cy="186.2" r=".51"/>
<circle cx="41.9" cy="182.9" r=".51"/>
</g>
<path d="M248.6 129.3v.8M248.6 130l-.2 .1M249.1 130.1h.5M249.6 129.3h-.3l-.2 .2 .1 .1 .4 .2M57.7 163.1l-.4 1.3" fill="none" stroke="#008484" stroke-width=".18"/>
<path d="M85.1 174h5.1v7.6h-5.1z" fill="#ffffc2"/>
<path d="M85.1 174h5.1v7.6h-5.1z" fill="none" stroke="#840000" stroke-width=".25"/>
<g fill="none" stroke="#840000" stroke-width=".18">
<path d="M16.5 31.8h.1M19 31.8h.1M22.9 29.2h.1M25.4 29.2h.1M26.7 29.2h3.8M26.7 31.8h3.8M35.6 29.2h3.8M35.6 31.8h3.8M39.4 31.8h.1M43.2 31.8v1.2h1.2l-1.2 1.3-1.3-1.3h1.3M43.2 31.8h.1M58.4 31.8h.1"/>
<path d="M58.4 24.1h.1M58.4 24.1v2.8M58.4 29v2.8M73.7 21.6h.1M73.7 21.6v2.5M73.7 26.7v3.8M73.7 35.6v1.2M106.7 38.1h.1M106.7 30.5v2.8M106.7 35.3v2.8M127 38.1h2.5M128.5 37.7h.7"/>
<path d="M142.2 33v2.6M154.9 38.1h2.6M166.4 38.1h2.5M179.1 33v2.6M182.9 22.9h.1M182.9 30.5h.1M182.9 22.9v2.8M182.9 27.7v2.8M200.7 38.1v2.5M24.1 52.1h.1M24.1 59.7h.1M24.1 49.5l-.7 1.3"/>
<path d="M24.1 49.5l.8 1.3M24.1 49.5v5.4M24.1 56.9v2.8M55.9 58.4h.1M55.9 58.4v2.8M61 58.4h2.5M73.7 58.4h2.5M77.5 58.4h.1M80 58.4h.1M80 58.4v2.8M104.1 53.3h2.6M111.8 45.7v2.6"/>
<path d="M111.8 58.4v2.6M116.8 53.3h3.8M125.7 53.3h3.8M127 40.6h2.5M127 43.2h2.5M127 45.7h2.5M127 50.8h2.5M142.2 55.9v2.5M154.9 40.6h2.6M154.9 43.2h2.6M154.9 53.3h2.6M154.9 50.8h2.6"/>
<path d="M166.4 40.6h2.5M166.4 48.3h2.5M179.1 50.8v2.5M189.2 40.6h2.6M189.2 43.2h2.6M189.2 45.7h2.6M195.6 47v2.8M195.6 51.8v2.8M196.8 43.2h2.6M200.7 45.7v2.6M55.9 63.2v2.8M61 61h2.5"/>
<path d="M68.6 66v2.6M80 63.2v2.8M27.9 98.8v2.8h5.1M33 94h-5.1v2.8M48.3 86.4h.1M48.3 86.4v5M48.3 86.4h2.8M53.1 86.4h2.8M63.5 94h5.1v2.8M68.6 98.8v2.8h-5.1M127 95.3v1.2M177.8 96.5h3.8"/>
<path d="M181.6 99.1h-3.8v1.2M185.4 92.7h.1M185.4 94v1.4M188 97.8h3.8M240 92.7h3.8M240 95.3h3.8M240 97.8h3.8M248.9 92.7h3.8M248.9 95.3h3.8M248.9 97.8h3.8M256.5 95.3h.1M260.3 97.8h.1"/>
<path d="M27.9 119.4h5.1M30.7 119h.7M63.5 114.3h7.9M63.5 106.7h7.9M63.5 119.4h5.1M73.4 114.3h2.8M73.4 106.7h2.8M81.3 114.3h.1M106.7 113h2.5M106.7 115.6h2.5M106.7 118.1h2.5M116.8 102.9v2.5"/>
<path d="M119.4 102.9v2.5M121.9 102.9v2.5M124.5 102.9v2.5M127 101.6v3.8M129.5 102.9v2.5M132.1 102.9v2.5M139.7 113h2.5M139.7 115.6h2.5M139.7 118.1h2.5M141.2 112.6h.7M177.8 105.4v1.3M185.4 100.2v1.4"/>
<path d="M238.8 104.1h.1M240 100.3h3.8M240 102.9h3.8M248.9 100.3h3.8M248.9 102.9h3.8M27.9 124.5h5.1M27.9 129.5h5.1M27.9 134.6h5.1M63.5 124.5h5.1M63.5 129.5h5.1M63.5 134.6h5.1M106.7 120.7h2.5"/>
<path d="M106.7 123.2h2.5M106.7 125.7h2.5M106.7 128.3h2.5M116.8 135.9v2.5M119.4 135.9v2.5M121.9 135.9v2.5M124 136.2v.7M124.5 135.9v2.5M127 135.9v2.5M129.5 135.9v2.5M132.1 135.9v2.5M139.7 120.7h2.5"/>
<path d="M139.7 123.2h2.5M139.7 125.7h2.5M139.7 128.3h2.5M182.9 133.4h.1M182.9 133.4v2.7M182.9 138.2v2.8M232.4 132.1v2.5M233.7 138.4h2.5M237.5 139.7h.1M237.5 133.4h.1M238.8 133.4h3.8M238.8 135.9h3.8"/>
<path d="M238.8 138.4h3.8M247.6 133.4h3.9M247.6 135.9h3.9M247.6 138.4h3.9M252.7 133.4h.1M48.3 147.3h.1M48.3 142.2v5.1M182.9 141h.1M232.4 142.2v2.6M40.6 167.6h.1M41.9 167.6h2.5M48.3 168.9v2.6"/>
<path d="M52.1 167.6h2.5M55.9 167.6h.1M81.3 175.3h3.8M81.3 177.8h3.8M85.1 175.1h1.3v.3h-1.3zM85.1 177.7h1.3v.2h-1.3zM88.9 175.1h1.3v.3h-1.3zM88.9 177.7h1.3v.2h-1.3zM90.2 175.3h3.8M90.2 177.8h3.8M119.4 174h3.8M119.4 176.5h3.8"/>
<path d="M119.4 179.1h3.8M128.3 174h3.8M128.3 176.5h3.8M128.3 179.1h3.8M81.3 180.3h3.8M85.1 180.2h1.3v.3h-1.3zM88.9 180.2h1.3v.3h-1.3zM90.2 180.3h3.8M95.2 181.6h.1M118.1 182.9v1.3M118.1 189.2v1.3M119.4 181.6h3.8"/>
<path d="M128.3 181.6h3.8M134.6 190.5h.1M134.6 182.9v1.3M134.6 189.2v1.3"/>
</g>
<g fill="none" stroke="#008484" stroke-width=".18">
<path d="M60.2 19.6l-.4 1.3M75.5 17.1l-.4 1.3M184.7 18.4l-.4 1.2M18.3 27.2l-.4 1.3M25.3 24.7l-.4 1.3M67.4 29.1h.4M67.4 28.5h.6M114.7 35.5h.4M114.7 34.9h.6M191.4 27.9h.4M191.4 27.2h.6M20.3 56.3h.6"/>
<path d="M25.9 47.6l-.4 1.2M57.7 53.9l-.4 1.3M75.1 52.7l.2-.1a.68 .68 0 0 1 .4 .7 .68 .68 0 0 1-.4 .6 .84 .84 0 0 1-.2-1.2zM83.1 53.9l-.4 1.3M136.3 49.8h3.8M143.3 52.3h3.9M151.6 47.2h2.6M153.5 43.1h.5M153.5 42.5h.7M196.2 52.2v.6M115.1 65.3h.6M115.5 65.8l.3 .3v.3l-.3 .2"/>
<path d="M117 65.9l-.3 .2h-.3l-.2-.2 .2-.5 .3-.1 .2 .2a.84 .84 0 0 1-.3 1.1h-.2M149.3 65.3l.2 .3-.2 .4 .2 .1 .1 .3-.3 .2h-.5M150.1 65.3h.4l.3 .3-.3 .4 .3 .1v.3l-.2 .2h-.5zM150.1 66h.4M186.5 65.4l-.5-.1-.2 .2v.3l.6 .3 .1 .3-.2 .2h-.5M187.8 65.3v1.3l-.7-1.3v1.3M23.7 99h.5M23.7 98.4h.6M36.9 94.1h1M41.9 88.2l.3 .3-.1 .3-.7 .7h.8M49.7 81.9l-.4 1.2M59.3 85h.4"/>
<path d="M59.3 84.4h.6M61.1 94.1h1M77.1 99h.4M77.1 98.4h.6M182.4 92l.4 .1 .1 .3-.8 .9h.8M188.6 88.2l-.5 1.3M258.4 90.7l-.5 1.3M262.8 93.3l-.5 1.3M36.9 101.7h1M61.1 101.7h1M61.1 114.4h1M79.6 112.9h.4"/>
<path d="M79.6 112.3h.6M79.6 105.3h.4M79.6 104.7h.6M110.7 102.2h.6M110.8 102.7h.3l.3 .2-.1 .4-.5 .1M135.3 122.1h3.2M179.1 137.6h.6M184.7 128.8l-.4 1.3M239.3 128.8l-.4 1.3M248.6 129.3v.8M248.6 130l-.2 .1M249.1 130.1h.5"/>
<path d="M249.6 129.3h-.3l-.2 .2 .1 .1 .4 .2M255.1 128.8l-.4 1.3M43.1 163.1l-.5 1.3M57.7 163.1l-.4 1.3M94 170.8v1l.2 .2M126.6 169.5v1.1l.2 .2"/>
</g>
<path d="M157.3 46.2h7.6M228.8 53.8h6.4M256.3 41.1h7.6M256.4 46.2h7.5M77.6 132.9l.9 1.3M78.5 132.9l-.9 1.3M148.4 121.1h7.6M27.7 179.9l.8 1.3M28.5 179.9l-.8 1.3M73.9 175.8h6.3" fill="none" stroke="#000" stroke-width=".18"/>
<g fill="none" stroke="#008400" stroke-width=".18">
<path d="M265.4 17.8h-12.7v2.5M16.5 31.8h10.2M22.9 29.2h3.8M39.4 29.2h3.8v2.6h-3.8M73.7 36.8v1.3M119.4 38.1h7.6M142.2 33v-2.5h-41.9v19M157.5 38.1h3.8l2.5 2.5h2.6M166.4 38.1h-2.6l-2.5 2.5h-3.8M182.9 22.9h-3.8v10.1M200.7 35.6v2.5M207 27.9h-14v12.7h-1.2"/>
<path d="M228.6 30.5h11.4M228.6 22.9h11.4M228.6 20.3h11.4M240 27.9h-12.7v42M252.7 27.9h11.5M252.7 38.1h11.5M252.7 35.6h11.5M252.7 22.9h12.7v47h-12.7M252.7 33h12.7M252.7 25.4h11.5M24.1 52.1h3.8v2.5h2.6M30.5 57.2h-2.6v2.5h-3.8"/>
<path d="M55.9 58.4h5.1v2.6M76.2 58.4h3.8M100.3 45.7h11.5M119.4 45.7h7.6M119.4 43.2h7.6M119.4 40.6h7.6M142.2 58.4v2.6M157.5 48.3h7.6M166.4 48.3v12.7M179.1 53.3v7.7M191.8 45.7v12.7h16.5M191.8 43.2h5"/>
<path d="M195.6 54.6v6.4h-95.3v-3.8M195.6 43.2v3.8M200.7 48.3v2.5M227.3 48.3h12.7M228.6 50.8h11.4M228.6 53.3h11.4M228.6 55.9h11.4M228.6 58.4h11.4M228.6 45.7h11.4M228.6 43.2h11.4M228.6 40.6h11.4M252.7 50.8h11.5"/>
<path d="M252.7 53.3h12.7M252.7 55.9h11.5M252.7 58.4h12.7M252.7 48.3h11.5M252.7 45.7h11.5M252.7 43.2h11.5M252.7 40.6h12.7M55.9 66v2.6h24.1v-2.6M227.3 66h12.7M228.6 63.5h11.4M252.7 63.5h11.5M252.7 66h11.5"/>
<path d="M147.3 95.3h-47v15.2h3.8v2.5h2.6M167.6 96.5h10.2M167.6 99.1h10.2M185.4 94v-1.3h14v1.3M191.8 97.8h3.8M232.4 92.7h7.6M232.4 97.8h7.6M240 95.3h-1.2v8.8M252.7 97.8h7.6M252.7 95.3h3.8M76.2 106.7h5.1v7.6h-5.1M106.7 115.6h-2.6v2.5h-3.8v22.9h61v-12.7"/>
<path d="M132.1 102.9v-2.6h12.7v40.7M147.3 102.9v20.3M185.4 101.6v5.1M199.4 101.6v5.1h-21.6M232.4 102.9h7.6M238.8 100.3h1.2M252.7 100.3h7.6M252.7 102.9h7.6M17.8 134.6h10.1M17.8 124.5h10.1M68.6 134.6h10.1M68.6 124.5h10.1"/>
<path d="M119.4 138.4v6.4h-10.2M121.9 138.4v8.9h-12.7M132.1 138.4v2.6M142.2 128.3h16.5M142.2 125.7h2.6M142.2 123.2h14M182.9 133.4h3.8v1.2h5.1M186.7 137.2h5.1M191.8 139.7h-5.1v1.3h-3.8M232.4 125.7v6.4M236.2 138.4h2.6M237.5 133.4h1.3"/>
<path d="M238.8 135.9h-1.3v3.8M251.5 135.9h5M251.5 133.4h1.2M251.5 138.4h5M260.3 125.7v6.4M232.4 144.8v5.1M260.3 144.8v5.1M19 165.1h10.2v1.3M29.2 179.1v2.5h-10.2M31.7 176.5h10.2M33 172.7h14v3.8h1.3M40.6 167.6h1.3"/>
<path d="M48.3 179.1h-1.3v3.8h-1.3M48.3 171.5v2.5M54.6 167.6h1.3M73.7 175.3h7.6M73.7 177.8h7.6M94 175.3h8.9M94 177.8h1.2v3.8M109.2 179.1h10.2M109.2 174h10.2M109.2 176.5h10.2M132.1 179.1h12.7M132.1 174h12.7"/>
<path d="M134.6 174v8.9M41.9 189.2v1.3h-10.2M48.3 181.6v5.1M73.7 180.3h7.6M94 180.3h8.9M109.2 181.6h10.2M118.1 190.5h16.5M118.1 181.6v1.3M132.1 181.6v8.9"/>
</g>
<g fill="none" stroke="#000084" stroke-width=".18">
<path d="M239.4 17.2l1.2 1.2M240.6 17.2l-1.2 1.2M239.4 32.4l1.2 1.2M239.4 35l1.2 1.2M239.4 37.5l1.2 1.2M239.4 24.8l1.2 1.2M240.6 32.4l-1.2 1.2M240.6 24.8l-1.2 1.2M240.6 35l-1.2 1.2M240.6 37.5l-1.2 1.2M252.1 29.9l1.2 1.2M253.3 29.9l-1.2 1.2"/>
<path d="M103.5 52.7l1.2 1.2M104.7 52.7l-1.2 1.2M126.4 50.2l1.2 1.2M127.6 50.2l-1.2 1.2M156.9 52.7l1.2 1.2M156.9 42.6l1.2 1.2M156.9 50.2l1.2 1.2M158.1 52.7l-1.2 1.2M158.1 42.6l-1.2 1.2M158.1 50.2l-1.2 1.2M239.4 60.4l1.2 1.2M240.6 60.4l-1.2 1.2"/>
<path d="M252.1 60.4l1.2 1.2M253.3 60.4l-1.2 1.2M252.1 92.1l1.2 1.2M253.3 92.1l-1.2 1.2M27.3 118.8l1.2 1.2M28.5 118.8l-1.2 1.2M68 118.8l1.2 1.2M69.2 118.8l-1.2 1.2M106.1 117.5l1.2 1.2M107.3 117.5l-1.2 1.2M116.2 102.3l1.2 1.2M117.4 102.3l-1.2 1.2"/>
<path d="M118.8 102.3l1.2 1.2M120 102.3l-1.2 1.2M121.3 102.3l1.2 1.2M122.5 102.3l-1.2 1.2M123.9 102.3l1.2 1.2M125.1 102.3l-1.2 1.2M128.9 102.3l1.2 1.2M130.1 102.3l-1.2 1.2M141.6 115l1.2 1.2M141.6 112.4l1.2 1.2M141.6 117.5l1.2 1.2M142.8 112.4l-1.2 1.2"/>
<path d="M142.8 115l-1.2 1.2M142.8 117.5l-1.2 1.2M27.3 128.9l1.2 1.2M28.5 128.9l-1.2 1.2M68 128.9l1.2 1.2M69.2 128.9l-1.2 1.2M106.1 127.7l1.2 1.2M106.1 120l1.2 1.3M106.1 122.6l1.2 1.2M106.1 125.1l1.2 1.2M107.3 120l-1.2 1.3M107.3 127.7l-1.2 1.2"/>
<path d="M107.3 122.6l-1.2 1.2M107.3 125.1l-1.2 1.2M116.2 137.8l1.2 1.2M117.4 137.8l-1.2 1.2M123.9 137.8l1.2 1.2M125.1 137.8l-1.2 1.2M126.4 137.8l1.2 1.2M127.6 137.8l-1.2 1.2M128.9 137.8l1.2 1.2M130.1 137.8l-1.2 1.2M141.6 120l1.2 1.3M142.8 120l-1.2 1.3"/>
<path d="M131.5 175.9l1.2 1.2M132.7 175.9l-1.2 1.2"/>
</g>
<g fill="none" stroke="#0000c2" stroke-width=".18">
<path d="M12.7 12.7h77.5v31.8h-77.5zM91.4 12.7h119.4v63.5h-119.4zM101.1 14.1l.3 .9M101.4 15l-.3 .4M101.7 14.1l-.3 .9M212.1 12.7h72.4v63.5h-72.4zM221.7 14.1l.3 .9M222 15l-.3 .4M222.3 14.1l-.3 .9M12.7 45.7h33v30.5h-33zM47 45.7h43.2v30.5h-43.2zM61.8 47.1v.9"/>
<path d="M62.1 47.1l-.3 .3M12.7 77.5h77.5v77.4h-77.5zM18.8 79.7h.8M19.6 78.6v.4M29.4 78.9v.8M29.7 78.9l-.3 .2M91.4 77.5h72.4v77.4h-72.4zM98.9 78.5h.6M99 79h.3l.3 .2-.1 .4-.5 .1M165.1 77.5h45.7v40.6h-45.7zM178.5 78.9h.5M178.7 78.5v1.1l.3 .1"/>
<path d="M212.1 77.5h72.4v40.6h-72.4zM165.1 119.4h45.7v35.5h-45.7zM212.1 119.4h72.4v35.5h-72.4zM221.4 120.8v.9M221.4 121.5l-.2 .2M222.4 120.9l-.3-.1-.2 .2 .1 .2 .4 .1v.3h-.5M232.8 120.2a1.46 1.46 0 0 1 0 1.9M12.7 156.2h57.1v40.7h-57.1zM18.9 157.2v1.1l.2 .2M71.1 156.2h34.3v40.7h-34.3zM85.3 157.2v1.1l.2 .2M106.7 156.2h41.9v40.7h-41.9z"/>
<path d="M112.7 157.2v1.1l.2 .2M149.9 156.2h26.6v40.7h-26.6zM157.6 157.6l.3 .1M157.9 157.6v1.1l-.1 .1-.3 .1M157.9 158.4l-.3 .1"/>
</g>
<g fill="#008400" stroke="#008400" stroke-width=".18">
<circle cx="265.4" cy="58.4" r=".46"/>
<circle cx="265.4" cy="69.9" r=".46"/>
<circle cx="166.4" cy="61" r=".46"/>
<circle cx="179.1" cy="61" r=".46"/>
<circle cx="195.6" cy="43.2" r=".46"/>
<circle cx="200.7" cy="58.4" r=".46"/>
<circle cx="252.7" cy="17.8" r=".46"/>
<circle cx="265.4" cy="33" r=".46"/>
<circle cx="265.4" cy="40.6" r=".46"/>
<circle cx="265.4" cy="53.3" r=".46"/>
<circle cx="238.8" cy="100.3" r=".46"/>
<circle cx="227.3" cy="48.3" r=".46"/>
<circle cx="227.3" cy="66" r=".46"/>
<circle cx="185.4" cy="92.7" r=".46"/>
<circle cx="182.9" cy="141" r=".46"/>
<circle cx="185.4" cy="106.7" r=".46"/>
<circle cx="182.9" cy="133.4" r=".46"/>
<circle cx="134.6" cy="174" r=".46"/>
<circle cx="134.6" cy="190.5" r=".46"/>
<circle cx="132.1" cy="190.5" r=".46"/>
<circle cx="118.1" cy="181.6" r=".46"/>
<circle cx="100.3" cy="141" r=".46"/>
<circle cx="144.8" cy="125.7" r=".46"/>
<circle cx="100.3" cy="110.5" r=".46"/>
<circle cx="177.8" cy="99.1" r=".46"/>
<circle cx="132.1" cy="141" r=".46"/>
<circle cx="147.3" cy="123.2" r=".46"/>
<circle cx="144.8" cy="141" r=".46"/>
<circle cx="142.2" cy="61" r=".46"/>
<circle cx="127" cy="95.3" r=".46"/>
<circle cx="100.3" cy="61" r=".46"/>
<circle cx="111.8" cy="61" r=".46"/>
<circle cx="106.7" cy="30.5" r=".46"/>
<circle cx="100.3" cy="45.7" r=".46"/>
<circle cx="100.3" cy="30.5" r=".46"/>
<circle cx="182.9" cy="22.9" r=".46"/>
<circle cx="200.7" cy="27.9" r=".46"/>
<circle cx="24.1" cy="52.1" r=".46"/>
<circle cx="24.1" cy="59.7" r=".46"/>
<circle cx="25.4" cy="29.2" r=".46"/>
<circle cx="43.2" cy="31.8" r=".46"/>
<circle cx="19" cy="31.8" r=".46"/>
<circle cx="48.3" cy="86.4" r=".46"/>
<circle cx="68.6" cy="68.6" r=".46"/>
<circle cx="55.9" cy="68.6" r=".46"/>
<circle cx="39.4" cy="31.8" r=".46"/>
<circle cx="77.5" cy="58.4" r=".46"/>
<circle cx="80" cy="58.4" r=".46"/>
<circle cx="55.9" cy="58.4" r=".46"/>
<circle cx="61" cy="58.4" r=".46"/>
<circle cx="100.3" cy="95.3" r=".46"/>
<circle cx="81.3" cy="114.3" r=".46"/>
<circle cx="100.3" cy="118.1" r=".46"/>
</g>
<use href="#words"/>
</svg>
